VERSION 5.8 ;
BUSBITCHARS "[]" ;
DIVIDERCHAR "/" ;
UNITS
    DATABASE MICRONS 1000 ;
END UNITS

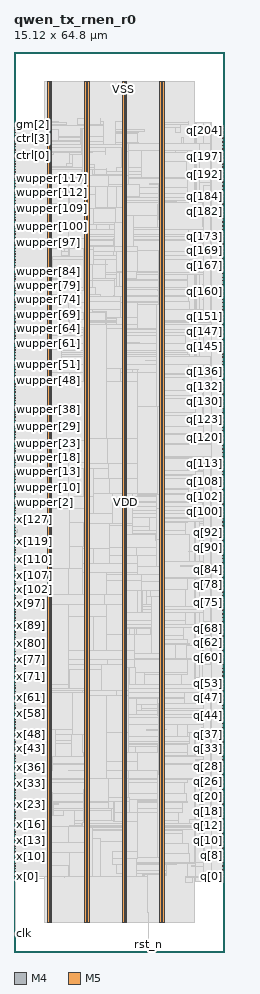
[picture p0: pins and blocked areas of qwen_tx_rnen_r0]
MACRO qwen_tx_rnen_r0
  FOREIGN qwen_tx_rnen_r0 0 0 ;
  CLASS BLOCK ;
  SIZE 15.12 BY 64.8 ;
  PIN clk
    DIRECTION INPUT ;
    USE SIGNAL ;
    PORT
      LAYER M4 ;
        RECT  0.054 1.296 0.138 1.32 ;
    END
    PORT
      LAYER M4 ;
        RECT  0.108 1.296 0.227 1.416 ;
    END
  END clk
  PIN ctrl[0]
    DIRECTION INPUT ;
    USE SIGNAL ;
    PORT
      LAYER M4 ;
        RECT  0.054 57.36 0.138 57.384 ;
    END
  END ctrl[0]
  PIN ctrl[1]
    DIRECTION INPUT ;
    USE SIGNAL ;
    PORT
      LAYER M4 ;
        RECT  0.054 57.552 0.138 57.576 ;
    END
  END ctrl[1]
  PIN ctrl[2]
    DIRECTION INPUT ;
    USE SIGNAL ;
    PORT
      LAYER M4 ;
        RECT  0.054 57.744 0.138 57.768 ;
    END
  END ctrl[2]
  PIN ctrl[3]
    DIRECTION INPUT ;
    USE SIGNAL ;
    PORT
      LAYER M4 ;
        RECT  0.054 57.984 0.138 58.008 ;
    END
  END ctrl[3]
  PIN ctrl[4]
    DIRECTION INPUT ;
    USE SIGNAL ;
    PORT
      LAYER M4 ;
        RECT  0.054 58.176 0.138 58.2 ;
    END
  END ctrl[4]
  PIN ctrl[5]
    DIRECTION INPUT ;
    USE SIGNAL ;
    PORT
      LAYER M4 ;
        RECT  0.054 58.368 0.138 58.392 ;
    END
  END ctrl[5]
  PIN gm[0]
    DIRECTION INPUT ;
    USE SIGNAL ;
    PORT
      LAYER M4 ;
        RECT  0.054 58.56 0.138 58.584 ;
    END
  END gm[0]
  PIN gm[1]
    DIRECTION INPUT ;
    USE SIGNAL ;
    PORT
      LAYER M4 ;
        RECT  0.054 58.8 0.138 58.824 ;
    END
  END gm[1]
  PIN gm[2]
    DIRECTION INPUT ;
    USE SIGNAL ;
    PORT
      LAYER M4 ;
        RECT  0.054 58.992 0.138 59.016 ;
    END
  END gm[2]
  PIN gm[3]
    DIRECTION INPUT ;
    USE SIGNAL ;
    PORT
      LAYER M4 ;
        RECT  0.054 59.184 0.138 59.208 ;
    END
  END gm[3]
  PIN q[0]
    DIRECTION OUTPUT ;
    USE SIGNAL ;
    PORT
      LAYER M4 ;
        RECT  14.982 5.424 15.066 5.448 ;
    END
  END q[0]
  PIN q[100]
    DIRECTION OUTPUT ;
    USE SIGNAL ;
    PORT
      LAYER M4 ;
        RECT  14.982 31.728 15.066 31.752 ;
    END
  END q[100]
  PIN q[101]
    DIRECTION OUTPUT ;
    USE SIGNAL ;
    PORT
      LAYER M4 ;
        RECT  14.982 32.016 15.066 32.04 ;
    END
  END q[101]
  PIN q[102]
    DIRECTION OUTPUT ;
    USE SIGNAL ;
    PORT
      LAYER M4 ;
        RECT  14.982 32.256 15.066 32.28 ;
    END
  END q[102]
  PIN q[103]
    DIRECTION OUTPUT ;
    USE SIGNAL ;
    PORT
      LAYER M4 ;
        RECT  14.982 32.496 15.066 32.52 ;
    END
  END q[103]
  PIN q[104]
    DIRECTION OUTPUT ;
    USE SIGNAL ;
    PORT
      LAYER M4 ;
        RECT  14.982 32.784 15.066 32.808 ;
    END
  END q[104]
  PIN q[105]
    DIRECTION OUTPUT ;
    USE SIGNAL ;
    PORT
      LAYER M4 ;
        RECT  14.982 33.024 15.066 33.048 ;
    END
  END q[105]
  PIN q[106]
    DIRECTION OUTPUT ;
    USE SIGNAL ;
    PORT
      LAYER M4 ;
        RECT  14.982 33.312 15.066 33.336 ;
    END
  END q[106]
  PIN q[107]
    DIRECTION OUTPUT ;
    USE SIGNAL ;
    PORT
      LAYER M4 ;
        RECT  14.982 33.552 15.066 33.576 ;
    END
  END q[107]
  PIN q[108]
    DIRECTION OUTPUT ;
    USE SIGNAL ;
    PORT
      LAYER M4 ;
        RECT  14.982 33.84 15.066 33.864 ;
    END
  END q[108]
  PIN q[109]
    DIRECTION OUTPUT ;
    USE SIGNAL ;
    PORT
      LAYER M4 ;
        RECT  14.982 34.08 15.066 34.104 ;
    END
  END q[109]
  PIN q[10]
    DIRECTION OUTPUT ;
    USE SIGNAL ;
    PORT
      LAYER M4 ;
        RECT  14.982 8.016 15.066 8.04 ;
    END
  END q[10]
  PIN q[110]
    DIRECTION OUTPUT ;
    USE SIGNAL ;
    PORT
      LAYER M4 ;
        RECT  14.982 34.368 15.066 34.392 ;
    END
  END q[110]
  PIN q[111]
    DIRECTION OUTPUT ;
    USE SIGNAL ;
    PORT
      LAYER M4 ;
        RECT  14.982 34.608 15.066 34.632 ;
    END
  END q[111]
  PIN q[112]
    DIRECTION OUTPUT ;
    USE SIGNAL ;
    PORT
      LAYER M4 ;
        RECT  14.982 34.896 15.066 34.92 ;
    END
  END q[112]
  PIN q[113]
    DIRECTION OUTPUT ;
    USE SIGNAL ;
    PORT
      LAYER M4 ;
        RECT  14.982 35.136 15.066 35.16 ;
    END
  END q[113]
  PIN q[114]
    DIRECTION OUTPUT ;
    USE SIGNAL ;
    PORT
      LAYER M4 ;
        RECT  14.982 35.424 15.066 35.448 ;
    END
  END q[114]
  PIN q[115]
    DIRECTION OUTPUT ;
    USE SIGNAL ;
    PORT
      LAYER M4 ;
        RECT  14.982 35.664 15.066 35.688 ;
    END
  END q[115]
  PIN q[116]
    DIRECTION OUTPUT ;
    USE SIGNAL ;
    PORT
      LAYER M4 ;
        RECT  14.982 35.952 15.066 35.976 ;
    END
  END q[116]
  PIN q[117]
    DIRECTION OUTPUT ;
    USE SIGNAL ;
    PORT
      LAYER M4 ;
        RECT  14.982 36.192 15.066 36.216 ;
    END
  END q[117]
  PIN q[118]
    DIRECTION OUTPUT ;
    USE SIGNAL ;
    PORT
      LAYER M4 ;
        RECT  14.982 36.48 15.066 36.504 ;
    END
  END q[118]
  PIN q[119]
    DIRECTION OUTPUT ;
    USE SIGNAL ;
    PORT
      LAYER M4 ;
        RECT  14.982 36.72 15.066 36.744 ;
    END
  END q[119]
  PIN q[11]
    DIRECTION OUTPUT ;
    USE SIGNAL ;
    PORT
      LAYER M4 ;
        RECT  14.982 8.304 15.066 8.328 ;
    END
  END q[11]
  PIN q[120]
    DIRECTION OUTPUT ;
    USE SIGNAL ;
    PORT
      LAYER M4 ;
        RECT  14.982 37.008 15.066 37.032 ;
    END
  END q[120]
  PIN q[121]
    DIRECTION OUTPUT ;
    USE SIGNAL ;
    PORT
      LAYER M4 ;
        RECT  14.982 37.248 15.066 37.272 ;
    END
  END q[121]
  PIN q[122]
    DIRECTION OUTPUT ;
    USE SIGNAL ;
    PORT
      LAYER M4 ;
        RECT  14.982 37.536 15.066 37.56 ;
    END
  END q[122]
  PIN q[123]
    DIRECTION OUTPUT ;
    USE SIGNAL ;
    PORT
      LAYER M4 ;
        RECT  14.982 37.776 15.066 37.8 ;
    END
  END q[123]
  PIN q[124]
    DIRECTION OUTPUT ;
    USE SIGNAL ;
    PORT
      LAYER M4 ;
        RECT  14.982 38.064 15.066 38.088 ;
    END
  END q[124]
  PIN q[125]
    DIRECTION OUTPUT ;
    USE SIGNAL ;
    PORT
      LAYER M4 ;
        RECT  14.982 38.304 15.066 38.328 ;
    END
  END q[125]
  PIN q[126]
    DIRECTION OUTPUT ;
    USE SIGNAL ;
    PORT
      LAYER M4 ;
        RECT  14.982 38.592 15.066 38.616 ;
    END
  END q[126]
  PIN q[127]
    DIRECTION OUTPUT ;
    USE SIGNAL ;
    PORT
      LAYER M4 ;
        RECT  14.982 38.832 15.066 38.856 ;
    END
  END q[127]
  PIN q[128]
    DIRECTION OUTPUT ;
    USE SIGNAL ;
    PORT
      LAYER M4 ;
        RECT  14.982 39.12 15.066 39.144 ;
    END
  END q[128]
  PIN q[129]
    DIRECTION OUTPUT ;
    USE SIGNAL ;
    PORT
      LAYER M4 ;
        RECT  14.982 39.36 15.066 39.384 ;
    END
  END q[129]
  PIN q[12]
    DIRECTION OUTPUT ;
    USE SIGNAL ;
    PORT
      LAYER M4 ;
        RECT  14.982 8.544 15.066 8.568 ;
    END
  END q[12]
  PIN q[130]
    DIRECTION OUTPUT ;
    USE SIGNAL ;
    PORT
      LAYER M4 ;
        RECT  14.982 39.648 15.066 39.672 ;
    END
  END q[130]
  PIN q[131]
    DIRECTION OUTPUT ;
    USE SIGNAL ;
    PORT
      LAYER M4 ;
        RECT  14.982 39.888 15.066 39.912 ;
    END
  END q[131]
  PIN q[132]
    DIRECTION OUTPUT ;
    USE SIGNAL ;
    PORT
      LAYER M4 ;
        RECT  14.982 40.176 15.066 40.2 ;
    END
  END q[132]
  PIN q[133]
    DIRECTION OUTPUT ;
    USE SIGNAL ;
    PORT
      LAYER M4 ;
        RECT  14.982 40.416 15.066 40.44 ;
    END
  END q[133]
  PIN q[134]
    DIRECTION OUTPUT ;
    USE SIGNAL ;
    PORT
      LAYER M4 ;
        RECT  14.982 40.704 15.066 40.728 ;
    END
  END q[134]
  PIN q[135]
    DIRECTION OUTPUT ;
    USE SIGNAL ;
    PORT
      LAYER M4 ;
        RECT  14.982 40.944 15.066 40.968 ;
    END
  END q[135]
  PIN q[136]
    DIRECTION OUTPUT ;
    USE SIGNAL ;
    PORT
      LAYER M4 ;
        RECT  14.982 41.232 15.066 41.256 ;
    END
  END q[136]
  PIN q[137]
    DIRECTION OUTPUT ;
    USE SIGNAL ;
    PORT
      LAYER M4 ;
        RECT  14.982 41.472 15.066 41.496 ;
    END
  END q[137]
  PIN q[138]
    DIRECTION OUTPUT ;
    USE SIGNAL ;
    PORT
      LAYER M4 ;
        RECT  14.982 41.76 15.066 41.784 ;
    END
  END q[138]
  PIN q[139]
    DIRECTION OUTPUT ;
    USE SIGNAL ;
    PORT
      LAYER M4 ;
        RECT  14.982 42 15.066 42.024 ;
    END
  END q[139]
  PIN q[13]
    DIRECTION OUTPUT ;
    USE SIGNAL ;
    PORT
      LAYER M4 ;
        RECT  14.982 8.832 15.066 8.856 ;
    END
  END q[13]
  PIN q[140]
    DIRECTION OUTPUT ;
    USE SIGNAL ;
    PORT
      LAYER M4 ;
        RECT  14.982 42.288 15.066 42.312 ;
    END
  END q[140]
  PIN q[141]
    DIRECTION OUTPUT ;
    USE SIGNAL ;
    PORT
      LAYER M4 ;
        RECT  14.982 42.528 15.066 42.552 ;
    END
  END q[141]
  PIN q[142]
    DIRECTION OUTPUT ;
    USE SIGNAL ;
    PORT
      LAYER M4 ;
        RECT  14.982 42.816 15.066 42.84 ;
    END
  END q[142]
  PIN q[143]
    DIRECTION OUTPUT ;
    USE SIGNAL ;
    PORT
      LAYER M4 ;
        RECT  14.982 43.056 15.066 43.08 ;
    END
  END q[143]
  PIN q[144]
    DIRECTION OUTPUT ;
    USE SIGNAL ;
    PORT
      LAYER M4 ;
        RECT  14.982 43.296 15.066 43.32 ;
    END
  END q[144]
  PIN q[145]
    DIRECTION OUTPUT ;
    USE SIGNAL ;
    PORT
      LAYER M4 ;
        RECT  14.982 43.584 15.066 43.608 ;
    END
  END q[145]
  PIN q[146]
    DIRECTION OUTPUT ;
    USE SIGNAL ;
    PORT
      LAYER M4 ;
        RECT  14.982 43.824 15.066 43.848 ;
    END
  END q[146]
  PIN q[147]
    DIRECTION OUTPUT ;
    USE SIGNAL ;
    PORT
      LAYER M4 ;
        RECT  14.982 44.112 15.066 44.136 ;
    END
  END q[147]
  PIN q[148]
    DIRECTION OUTPUT ;
    USE SIGNAL ;
    PORT
      LAYER M4 ;
        RECT  14.982 44.352 15.066 44.376 ;
    END
  END q[148]
  PIN q[149]
    DIRECTION OUTPUT ;
    USE SIGNAL ;
    PORT
      LAYER M4 ;
        RECT  14.982 44.64 15.066 44.664 ;
    END
  END q[149]
  PIN q[14]
    DIRECTION OUTPUT ;
    USE SIGNAL ;
    PORT
      LAYER M4 ;
        RECT  14.982 9.072 15.066 9.096 ;
    END
  END q[14]
  PIN q[150]
    DIRECTION OUTPUT ;
    USE SIGNAL ;
    PORT
      LAYER M4 ;
        RECT  14.982 44.88 15.066 44.904 ;
    END
  END q[150]
  PIN q[151]
    DIRECTION OUTPUT ;
    USE SIGNAL ;
    PORT
      LAYER M4 ;
        RECT  14.982 45.168 15.066 45.192 ;
    END
  END q[151]
  PIN q[152]
    DIRECTION OUTPUT ;
    USE SIGNAL ;
    PORT
      LAYER M4 ;
        RECT  14.982 45.408 15.066 45.432 ;
    END
  END q[152]
  PIN q[153]
    DIRECTION OUTPUT ;
    USE SIGNAL ;
    PORT
      LAYER M4 ;
        RECT  14.982 45.696 15.066 45.72 ;
    END
  END q[153]
  PIN q[154]
    DIRECTION OUTPUT ;
    USE SIGNAL ;
    PORT
      LAYER M4 ;
        RECT  14.982 45.936 15.066 45.96 ;
    END
  END q[154]
  PIN q[155]
    DIRECTION OUTPUT ;
    USE SIGNAL ;
    PORT
      LAYER M4 ;
        RECT  14.982 46.224 15.066 46.248 ;
    END
  END q[155]
  PIN q[156]
    DIRECTION OUTPUT ;
    USE SIGNAL ;
    PORT
      LAYER M4 ;
        RECT  14.982 46.464 15.066 46.488 ;
    END
  END q[156]
  PIN q[157]
    DIRECTION OUTPUT ;
    USE SIGNAL ;
    PORT
      LAYER M4 ;
        RECT  14.982 46.752 15.066 46.776 ;
    END
  END q[157]
  PIN q[158]
    DIRECTION OUTPUT ;
    USE SIGNAL ;
    PORT
      LAYER M4 ;
        RECT  14.982 46.992 15.066 47.016 ;
    END
  END q[158]
  PIN q[159]
    DIRECTION OUTPUT ;
    USE SIGNAL ;
    PORT
      LAYER M4 ;
        RECT  14.982 47.28 15.066 47.304 ;
    END
  END q[159]
  PIN q[15]
    DIRECTION OUTPUT ;
    USE SIGNAL ;
    PORT
      LAYER M4 ;
        RECT  14.982 9.36 15.066 9.384 ;
    END
  END q[15]
  PIN q[160]
    DIRECTION OUTPUT ;
    USE SIGNAL ;
    PORT
      LAYER M4 ;
        RECT  14.982 47.52 15.066 47.544 ;
    END
  END q[160]
  PIN q[161]
    DIRECTION OUTPUT ;
    USE SIGNAL ;
    PORT
      LAYER M4 ;
        RECT  14.982 47.808 15.066 47.832 ;
    END
  END q[161]
  PIN q[162]
    DIRECTION OUTPUT ;
    USE SIGNAL ;
    PORT
      LAYER M4 ;
        RECT  14.982 48.048 15.066 48.072 ;
    END
  END q[162]
  PIN q[163]
    DIRECTION OUTPUT ;
    USE SIGNAL ;
    PORT
      LAYER M4 ;
        RECT  14.982 48.336 15.066 48.36 ;
    END
  END q[163]
  PIN q[164]
    DIRECTION OUTPUT ;
    USE SIGNAL ;
    PORT
      LAYER M4 ;
        RECT  14.982 48.576 15.066 48.6 ;
    END
  END q[164]
  PIN q[165]
    DIRECTION OUTPUT ;
    USE SIGNAL ;
    PORT
      LAYER M4 ;
        RECT  14.982 48.864 15.066 48.888 ;
    END
  END q[165]
  PIN q[166]
    DIRECTION OUTPUT ;
    USE SIGNAL ;
    PORT
      LAYER M4 ;
        RECT  14.982 49.104 15.066 49.128 ;
    END
  END q[166]
  PIN q[167]
    DIRECTION OUTPUT ;
    USE SIGNAL ;
    PORT
      LAYER M4 ;
        RECT  14.982 49.392 15.066 49.416 ;
    END
  END q[167]
  PIN q[168]
    DIRECTION OUTPUT ;
    USE SIGNAL ;
    PORT
      LAYER M4 ;
        RECT  14.982 49.632 15.066 49.656 ;
    END
  END q[168]
  PIN q[169]
    DIRECTION OUTPUT ;
    USE SIGNAL ;
    PORT
      LAYER M4 ;
        RECT  14.982 49.92 15.066 49.944 ;
    END
  END q[169]
  PIN q[16]
    DIRECTION OUTPUT ;
    USE SIGNAL ;
    PORT
      LAYER M4 ;
        RECT  14.982 9.6 15.066 9.624 ;
    END
  END q[16]
  PIN q[170]
    DIRECTION OUTPUT ;
    USE SIGNAL ;
    PORT
      LAYER M4 ;
        RECT  14.982 50.16 15.066 50.184 ;
    END
  END q[170]
  PIN q[171]
    DIRECTION OUTPUT ;
    USE SIGNAL ;
    PORT
      LAYER M4 ;
        RECT  14.982 50.448 15.066 50.472 ;
    END
  END q[171]
  PIN q[172]
    DIRECTION OUTPUT ;
    USE SIGNAL ;
    PORT
      LAYER M4 ;
        RECT  14.982 50.688 15.066 50.712 ;
    END
  END q[172]
  PIN q[173]
    DIRECTION OUTPUT ;
    USE SIGNAL ;
    PORT
      LAYER M4 ;
        RECT  14.982 50.976 15.066 51 ;
    END
  END q[173]
  PIN q[174]
    DIRECTION OUTPUT ;
    USE SIGNAL ;
    PORT
      LAYER M4 ;
        RECT  14.982 51.216 15.066 51.24 ;
    END
  END q[174]
  PIN q[175]
    DIRECTION OUTPUT ;
    USE SIGNAL ;
    PORT
      LAYER M4 ;
        RECT  14.982 51.504 15.066 51.528 ;
    END
  END q[175]
  PIN q[176]
    DIRECTION OUTPUT ;
    USE SIGNAL ;
    PORT
      LAYER M4 ;
        RECT  14.982 51.744 15.066 51.768 ;
    END
  END q[176]
  PIN q[177]
    DIRECTION OUTPUT ;
    USE SIGNAL ;
    PORT
      LAYER M4 ;
        RECT  14.982 52.032 15.066 52.056 ;
    END
  END q[177]
  PIN q[178]
    DIRECTION OUTPUT ;
    USE SIGNAL ;
    PORT
      LAYER M4 ;
        RECT  14.982 52.272 15.066 52.296 ;
    END
  END q[178]
  PIN q[179]
    DIRECTION OUTPUT ;
    USE SIGNAL ;
    PORT
      LAYER M4 ;
        RECT  14.982 52.56 15.066 52.584 ;
    END
  END q[179]
  PIN q[17]
    DIRECTION OUTPUT ;
    USE SIGNAL ;
    PORT
      LAYER M4 ;
        RECT  14.982 9.888 15.066 9.912 ;
    END
  END q[17]
  PIN q[180]
    DIRECTION OUTPUT ;
    USE SIGNAL ;
    PORT
      LAYER M4 ;
        RECT  14.982 52.8 15.066 52.824 ;
    END
  END q[180]
  PIN q[181]
    DIRECTION OUTPUT ;
    USE SIGNAL ;
    PORT
      LAYER M4 ;
        RECT  14.982 53.088 15.066 53.112 ;
    END
  END q[181]
  PIN q[182]
    DIRECTION OUTPUT ;
    USE SIGNAL ;
    PORT
      LAYER M4 ;
        RECT  14.982 53.328 15.066 53.352 ;
    END
  END q[182]
  PIN q[183]
    DIRECTION OUTPUT ;
    USE SIGNAL ;
    PORT
      LAYER M4 ;
        RECT  14.982 53.616 15.066 53.64 ;
    END
  END q[183]
  PIN q[184]
    DIRECTION OUTPUT ;
    USE SIGNAL ;
    PORT
      LAYER M4 ;
        RECT  14.982 53.856 15.066 53.88 ;
    END
  END q[184]
  PIN q[185]
    DIRECTION OUTPUT ;
    USE SIGNAL ;
    PORT
      LAYER M4 ;
        RECT  14.982 54.096 15.066 54.12 ;
    END
  END q[185]
  PIN q[186]
    DIRECTION OUTPUT ;
    USE SIGNAL ;
    PORT
      LAYER M4 ;
        RECT  14.982 54.384 15.066 54.408 ;
    END
  END q[186]
  PIN q[187]
    DIRECTION OUTPUT ;
    USE SIGNAL ;
    PORT
      LAYER M4 ;
        RECT  14.982 54.624 15.066 54.648 ;
    END
  END q[187]
  PIN q[188]
    DIRECTION OUTPUT ;
    USE SIGNAL ;
    PORT
      LAYER M4 ;
        RECT  14.982 54.912 15.066 54.936 ;
    END
  END q[188]
  PIN q[189]
    DIRECTION OUTPUT ;
    USE SIGNAL ;
    PORT
      LAYER M4 ;
        RECT  14.982 55.152 15.066 55.176 ;
    END
  END q[189]
  PIN q[18]
    DIRECTION OUTPUT ;
    USE SIGNAL ;
    PORT
      LAYER M4 ;
        RECT  14.982 10.128 15.066 10.152 ;
    END
  END q[18]
  PIN q[190]
    DIRECTION OUTPUT ;
    USE SIGNAL ;
    PORT
      LAYER M4 ;
        RECT  14.982 55.44 15.066 55.464 ;
    END
  END q[190]
  PIN q[191]
    DIRECTION OUTPUT ;
    USE SIGNAL ;
    PORT
      LAYER M4 ;
        RECT  14.982 55.68 15.066 55.704 ;
    END
  END q[191]
  PIN q[192]
    DIRECTION OUTPUT ;
    USE SIGNAL ;
    PORT
      LAYER M4 ;
        RECT  14.982 55.968 15.066 55.992 ;
    END
  END q[192]
  PIN q[193]
    DIRECTION OUTPUT ;
    USE SIGNAL ;
    PORT
      LAYER M4 ;
        RECT  14.982 56.208 15.066 56.232 ;
    END
  END q[193]
  PIN q[194]
    DIRECTION OUTPUT ;
    USE SIGNAL ;
    PORT
      LAYER M4 ;
        RECT  14.982 56.496 15.066 56.52 ;
    END
  END q[194]
  PIN q[195]
    DIRECTION OUTPUT ;
    USE SIGNAL ;
    PORT
      LAYER M4 ;
        RECT  14.982 56.736 15.066 56.76 ;
    END
  END q[195]
  PIN q[196]
    DIRECTION OUTPUT ;
    USE SIGNAL ;
    PORT
      LAYER M4 ;
        RECT  14.982 57.024 15.066 57.048 ;
    END
  END q[196]
  PIN q[197]
    DIRECTION OUTPUT ;
    USE SIGNAL ;
    PORT
      LAYER M4 ;
        RECT  14.982 57.264 15.066 57.288 ;
    END
  END q[197]
  PIN q[198]
    DIRECTION OUTPUT ;
    USE SIGNAL ;
    PORT
      LAYER M4 ;
        RECT  14.982 57.552 15.066 57.576 ;
    END
  END q[198]
  PIN q[199]
    DIRECTION OUTPUT ;
    USE SIGNAL ;
    PORT
      LAYER M4 ;
        RECT  14.982 57.792 15.066 57.816 ;
    END
  END q[199]
  PIN q[19]
    DIRECTION OUTPUT ;
    USE SIGNAL ;
    PORT
      LAYER M4 ;
        RECT  14.982 10.416 15.066 10.44 ;
    END
  END q[19]
  PIN q[1]
    DIRECTION OUTPUT ;
    USE SIGNAL ;
    PORT
      LAYER M4 ;
        RECT  14.982 5.664 15.066 5.688 ;
    END
  END q[1]
  PIN q[200]
    DIRECTION OUTPUT ;
    USE SIGNAL ;
    PORT
      LAYER M4 ;
        RECT  14.982 58.08 15.066 58.104 ;
    END
  END q[200]
  PIN q[201]
    DIRECTION OUTPUT ;
    USE SIGNAL ;
    PORT
      LAYER M4 ;
        RECT  14.982 58.32 15.066 58.344 ;
    END
  END q[201]
  PIN q[202]
    DIRECTION OUTPUT ;
    USE SIGNAL ;
    PORT
      LAYER M4 ;
        RECT  14.982 58.608 15.066 58.632 ;
    END
  END q[202]
  PIN q[203]
    DIRECTION OUTPUT ;
    USE SIGNAL ;
    PORT
      LAYER M4 ;
        RECT  14.982 58.848 15.066 58.872 ;
    END
  END q[203]
  PIN q[204]
    DIRECTION OUTPUT ;
    USE SIGNAL ;
    PORT
      LAYER M4 ;
        RECT  14.982 59.136 15.066 59.16 ;
    END
  END q[204]
  PIN q[205]
    DIRECTION OUTPUT ;
    USE SIGNAL ;
    PORT
      LAYER M4 ;
        RECT  14.982 59.376 15.066 59.4 ;
    END
  END q[205]
  PIN q[20]
    DIRECTION OUTPUT ;
    USE SIGNAL ;
    PORT
      LAYER M4 ;
        RECT  14.982 10.656 15.066 10.68 ;
    END
  END q[20]
  PIN q[21]
    DIRECTION OUTPUT ;
    USE SIGNAL ;
    PORT
      LAYER M4 ;
        RECT  14.982 10.896 15.066 10.92 ;
    END
  END q[21]
  PIN q[22]
    DIRECTION OUTPUT ;
    USE SIGNAL ;
    PORT
      LAYER M4 ;
        RECT  14.982 11.184 15.066 11.208 ;
    END
  END q[22]
  PIN q[23]
    DIRECTION OUTPUT ;
    USE SIGNAL ;
    PORT
      LAYER M4 ;
        RECT  14.982 11.424 15.066 11.448 ;
    END
  END q[23]
  PIN q[24]
    DIRECTION OUTPUT ;
    USE SIGNAL ;
    PORT
      LAYER M4 ;
        RECT  14.982 11.712 15.066 11.736 ;
    END
  END q[24]
  PIN q[25]
    DIRECTION OUTPUT ;
    USE SIGNAL ;
    PORT
      LAYER M4 ;
        RECT  14.982 11.952 15.066 11.976 ;
    END
  END q[25]
  PIN q[26]
    DIRECTION OUTPUT ;
    USE SIGNAL ;
    PORT
      LAYER M4 ;
        RECT  14.982 12.24 15.066 12.264 ;
    END
  END q[26]
  PIN q[27]
    DIRECTION OUTPUT ;
    USE SIGNAL ;
    PORT
      LAYER M4 ;
        RECT  14.982 12.48 15.066 12.504 ;
    END
  END q[27]
  PIN q[28]
    DIRECTION OUTPUT ;
    USE SIGNAL ;
    PORT
      LAYER M4 ;
        RECT  14.982 12.768 15.066 12.792 ;
    END
  END q[28]
  PIN q[29]
    DIRECTION OUTPUT ;
    USE SIGNAL ;
    PORT
      LAYER M4 ;
        RECT  14.982 13.008 15.066 13.032 ;
    END
  END q[29]
  PIN q[2]
    DIRECTION OUTPUT ;
    USE SIGNAL ;
    PORT
      LAYER M4 ;
        RECT  14.982 5.904 15.066 5.928 ;
    END
  END q[2]
  PIN q[30]
    DIRECTION OUTPUT ;
    USE SIGNAL ;
    PORT
      LAYER M4 ;
        RECT  14.982 13.296 15.066 13.32 ;
    END
  END q[30]
  PIN q[31]
    DIRECTION OUTPUT ;
    USE SIGNAL ;
    PORT
      LAYER M4 ;
        RECT  14.982 13.536 15.066 13.56 ;
    END
  END q[31]
  PIN q[32]
    DIRECTION OUTPUT ;
    USE SIGNAL ;
    PORT
      LAYER M4 ;
        RECT  14.982 13.824 15.066 13.848 ;
    END
  END q[32]
  PIN q[33]
    DIRECTION OUTPUT ;
    USE SIGNAL ;
    PORT
      LAYER M4 ;
        RECT  14.982 14.064 15.066 14.088 ;
    END
  END q[33]
  PIN q[34]
    DIRECTION OUTPUT ;
    USE SIGNAL ;
    PORT
      LAYER M4 ;
        RECT  14.982 14.352 15.066 14.376 ;
    END
  END q[34]
  PIN q[35]
    DIRECTION OUTPUT ;
    USE SIGNAL ;
    PORT
      LAYER M4 ;
        RECT  14.982 14.592 15.066 14.616 ;
    END
  END q[35]
  PIN q[36]
    DIRECTION OUTPUT ;
    USE SIGNAL ;
    PORT
      LAYER M4 ;
        RECT  14.982 14.88 15.066 14.904 ;
    END
  END q[36]
  PIN q[37]
    DIRECTION OUTPUT ;
    USE SIGNAL ;
    PORT
      LAYER M4 ;
        RECT  14.982 15.12 15.066 15.144 ;
    END
  END q[37]
  PIN q[38]
    DIRECTION OUTPUT ;
    USE SIGNAL ;
    PORT
      LAYER M4 ;
        RECT  14.982 15.408 15.066 15.432 ;
    END
  END q[38]
  PIN q[39]
    DIRECTION OUTPUT ;
    USE SIGNAL ;
    PORT
      LAYER M4 ;
        RECT  14.982 15.648 15.066 15.672 ;
    END
  END q[39]
  PIN q[3]
    DIRECTION OUTPUT ;
    USE SIGNAL ;
    PORT
      LAYER M4 ;
        RECT  14.982 6.192 15.066 6.216 ;
    END
  END q[3]
  PIN q[40]
    DIRECTION OUTPUT ;
    USE SIGNAL ;
    PORT
      LAYER M4 ;
        RECT  14.982 15.936 15.066 15.96 ;
    END
  END q[40]
  PIN q[41]
    DIRECTION OUTPUT ;
    USE SIGNAL ;
    PORT
      LAYER M4 ;
        RECT  14.982 16.176 15.066 16.2 ;
    END
  END q[41]
  PIN q[42]
    DIRECTION OUTPUT ;
    USE SIGNAL ;
    PORT
      LAYER M4 ;
        RECT  14.982 16.464 15.066 16.488 ;
    END
  END q[42]
  PIN q[43]
    DIRECTION OUTPUT ;
    USE SIGNAL ;
    PORT
      LAYER M4 ;
        RECT  14.982 16.704 15.066 16.728 ;
    END
  END q[43]
  PIN q[44]
    DIRECTION OUTPUT ;
    USE SIGNAL ;
    PORT
      LAYER M4 ;
        RECT  14.982 16.992 15.066 17.016 ;
    END
  END q[44]
  PIN q[45]
    DIRECTION OUTPUT ;
    USE SIGNAL ;
    PORT
      LAYER M4 ;
        RECT  14.982 17.232 15.066 17.256 ;
    END
  END q[45]
  PIN q[46]
    DIRECTION OUTPUT ;
    USE SIGNAL ;
    PORT
      LAYER M4 ;
        RECT  14.982 17.52 15.066 17.544 ;
    END
  END q[46]
  PIN q[47]
    DIRECTION OUTPUT ;
    USE SIGNAL ;
    PORT
      LAYER M4 ;
        RECT  14.982 17.76 15.066 17.784 ;
    END
  END q[47]
  PIN q[48]
    DIRECTION OUTPUT ;
    USE SIGNAL ;
    PORT
      LAYER M4 ;
        RECT  14.982 18.048 15.066 18.072 ;
    END
  END q[48]
  PIN q[49]
    DIRECTION OUTPUT ;
    USE SIGNAL ;
    PORT
      LAYER M4 ;
        RECT  14.982 18.288 15.066 18.312 ;
    END
  END q[49]
  PIN q[4]
    DIRECTION OUTPUT ;
    USE SIGNAL ;
    PORT
      LAYER M4 ;
        RECT  14.982 6.432 15.066 6.456 ;
    END
  END q[4]
  PIN q[50]
    DIRECTION OUTPUT ;
    USE SIGNAL ;
    PORT
      LAYER M4 ;
        RECT  14.982 18.576 15.066 18.6 ;
    END
  END q[50]
  PIN q[51]
    DIRECTION OUTPUT ;
    USE SIGNAL ;
    PORT
      LAYER M4 ;
        RECT  14.982 18.816 15.066 18.84 ;
    END
  END q[51]
  PIN q[52]
    DIRECTION OUTPUT ;
    USE SIGNAL ;
    PORT
      LAYER M4 ;
        RECT  14.982 19.104 15.066 19.128 ;
    END
  END q[52]
  PIN q[53]
    DIRECTION OUTPUT ;
    USE SIGNAL ;
    PORT
      LAYER M4 ;
        RECT  14.982 19.344 15.066 19.368 ;
    END
  END q[53]
  PIN q[54]
    DIRECTION OUTPUT ;
    USE SIGNAL ;
    PORT
      LAYER M4 ;
        RECT  14.982 19.632 15.066 19.656 ;
    END
  END q[54]
  PIN q[55]
    DIRECTION OUTPUT ;
    USE SIGNAL ;
    PORT
      LAYER M4 ;
        RECT  14.982 19.872 15.066 19.896 ;
    END
  END q[55]
  PIN q[56]
    DIRECTION OUTPUT ;
    USE SIGNAL ;
    PORT
      LAYER M4 ;
        RECT  14.982 20.16 15.066 20.184 ;
    END
  END q[56]
  PIN q[57]
    DIRECTION OUTPUT ;
    USE SIGNAL ;
    PORT
      LAYER M4 ;
        RECT  14.982 20.4 15.066 20.424 ;
    END
  END q[57]
  PIN q[58]
    DIRECTION OUTPUT ;
    USE SIGNAL ;
    PORT
      LAYER M4 ;
        RECT  14.982 20.688 15.066 20.712 ;
    END
  END q[58]
  PIN q[59]
    DIRECTION OUTPUT ;
    USE SIGNAL ;
    PORT
      LAYER M4 ;
        RECT  14.982 20.928 15.066 20.952 ;
    END
  END q[59]
  PIN q[5]
    DIRECTION OUTPUT ;
    USE SIGNAL ;
    PORT
      LAYER M4 ;
        RECT  14.982 6.72 15.066 6.744 ;
    END
  END q[5]
  PIN q[60]
    DIRECTION OUTPUT ;
    USE SIGNAL ;
    PORT
      LAYER M4 ;
        RECT  14.982 21.216 15.066 21.24 ;
    END
  END q[60]
  PIN q[61]
    DIRECTION OUTPUT ;
    USE SIGNAL ;
    PORT
      LAYER M4 ;
        RECT  14.982 21.456 15.066 21.48 ;
    END
  END q[61]
  PIN q[62]
    DIRECTION OUTPUT ;
    USE SIGNAL ;
    PORT
      LAYER M4 ;
        RECT  14.982 21.696 15.066 21.72 ;
    END
  END q[62]
  PIN q[63]
    DIRECTION OUTPUT ;
    USE SIGNAL ;
    PORT
      LAYER M4 ;
        RECT  14.982 21.984 15.066 22.008 ;
    END
  END q[63]
  PIN q[64]
    DIRECTION OUTPUT ;
    USE SIGNAL ;
    PORT
      LAYER M4 ;
        RECT  14.982 22.224 15.066 22.248 ;
    END
  END q[64]
  PIN q[65]
    DIRECTION OUTPUT ;
    USE SIGNAL ;
    PORT
      LAYER M4 ;
        RECT  14.982 22.512 15.066 22.536 ;
    END
  END q[65]
  PIN q[66]
    DIRECTION OUTPUT ;
    USE SIGNAL ;
    PORT
      LAYER M4 ;
        RECT  14.982 22.752 15.066 22.776 ;
    END
  END q[66]
  PIN q[67]
    DIRECTION OUTPUT ;
    USE SIGNAL ;
    PORT
      LAYER M4 ;
        RECT  14.982 23.04 15.066 23.064 ;
    END
  END q[67]
  PIN q[68]
    DIRECTION OUTPUT ;
    USE SIGNAL ;
    PORT
      LAYER M4 ;
        RECT  14.982 23.28 15.066 23.304 ;
    END
  END q[68]
  PIN q[69]
    DIRECTION OUTPUT ;
    USE SIGNAL ;
    PORT
      LAYER M4 ;
        RECT  14.982 23.568 15.066 23.592 ;
    END
  END q[69]
  PIN q[6]
    DIRECTION OUTPUT ;
    USE SIGNAL ;
    PORT
      LAYER M4 ;
        RECT  14.982 6.96 15.066 6.984 ;
    END
  END q[6]
  PIN q[70]
    DIRECTION OUTPUT ;
    USE SIGNAL ;
    PORT
      LAYER M4 ;
        RECT  14.982 23.808 15.066 23.832 ;
    END
  END q[70]
  PIN q[71]
    DIRECTION OUTPUT ;
    USE SIGNAL ;
    PORT
      LAYER M4 ;
        RECT  14.982 24.096 15.066 24.12 ;
    END
  END q[71]
  PIN q[72]
    DIRECTION OUTPUT ;
    USE SIGNAL ;
    PORT
      LAYER M4 ;
        RECT  14.982 24.336 15.066 24.36 ;
    END
  END q[72]
  PIN q[73]
    DIRECTION OUTPUT ;
    USE SIGNAL ;
    PORT
      LAYER M4 ;
        RECT  14.982 24.624 15.066 24.648 ;
    END
  END q[73]
  PIN q[74]
    DIRECTION OUTPUT ;
    USE SIGNAL ;
    PORT
      LAYER M4 ;
        RECT  14.982 24.864 15.066 24.888 ;
    END
  END q[74]
  PIN q[75]
    DIRECTION OUTPUT ;
    USE SIGNAL ;
    PORT
      LAYER M4 ;
        RECT  14.982 25.152 15.066 25.176 ;
    END
  END q[75]
  PIN q[76]
    DIRECTION OUTPUT ;
    USE SIGNAL ;
    PORT
      LAYER M4 ;
        RECT  14.982 25.392 15.066 25.416 ;
    END
  END q[76]
  PIN q[77]
    DIRECTION OUTPUT ;
    USE SIGNAL ;
    PORT
      LAYER M4 ;
        RECT  14.982 25.68 15.066 25.704 ;
    END
  END q[77]
  PIN q[78]
    DIRECTION OUTPUT ;
    USE SIGNAL ;
    PORT
      LAYER M4 ;
        RECT  14.982 25.92 15.066 25.944 ;
    END
  END q[78]
  PIN q[79]
    DIRECTION OUTPUT ;
    USE SIGNAL ;
    PORT
      LAYER M4 ;
        RECT  14.982 26.208 15.066 26.232 ;
    END
  END q[79]
  PIN q[7]
    DIRECTION OUTPUT ;
    USE SIGNAL ;
    PORT
      LAYER M4 ;
        RECT  14.982 7.248 15.066 7.272 ;
    END
  END q[7]
  PIN q[80]
    DIRECTION OUTPUT ;
    USE SIGNAL ;
    PORT
      LAYER M4 ;
        RECT  14.982 26.448 15.066 26.472 ;
    END
  END q[80]
  PIN q[81]
    DIRECTION OUTPUT ;
    USE SIGNAL ;
    PORT
      LAYER M4 ;
        RECT  14.982 26.736 15.066 26.76 ;
    END
  END q[81]
  PIN q[82]
    DIRECTION OUTPUT ;
    USE SIGNAL ;
    PORT
      LAYER M4 ;
        RECT  14.982 26.976 15.066 27 ;
    END
  END q[82]
  PIN q[83]
    DIRECTION OUTPUT ;
    USE SIGNAL ;
    PORT
      LAYER M4 ;
        RECT  14.982 27.264 15.066 27.288 ;
    END
  END q[83]
  PIN q[84]
    DIRECTION OUTPUT ;
    USE SIGNAL ;
    PORT
      LAYER M4 ;
        RECT  14.982 27.504 15.066 27.528 ;
    END
  END q[84]
  PIN q[85]
    DIRECTION OUTPUT ;
    USE SIGNAL ;
    PORT
      LAYER M4 ;
        RECT  14.982 27.792 15.066 27.816 ;
    END
  END q[85]
  PIN q[86]
    DIRECTION OUTPUT ;
    USE SIGNAL ;
    PORT
      LAYER M4 ;
        RECT  14.982 28.032 15.066 28.056 ;
    END
  END q[86]
  PIN q[87]
    DIRECTION OUTPUT ;
    USE SIGNAL ;
    PORT
      LAYER M4 ;
        RECT  14.982 28.32 15.066 28.344 ;
    END
  END q[87]
  PIN q[88]
    DIRECTION OUTPUT ;
    USE SIGNAL ;
    PORT
      LAYER M4 ;
        RECT  14.982 28.56 15.066 28.584 ;
    END
  END q[88]
  PIN q[89]
    DIRECTION OUTPUT ;
    USE SIGNAL ;
    PORT
      LAYER M4 ;
        RECT  14.982 28.848 15.066 28.872 ;
    END
  END q[89]
  PIN q[8]
    DIRECTION OUTPUT ;
    USE SIGNAL ;
    PORT
      LAYER M4 ;
        RECT  14.982 7.488 15.066 7.512 ;
    END
  END q[8]
  PIN q[90]
    DIRECTION OUTPUT ;
    USE SIGNAL ;
    PORT
      LAYER M4 ;
        RECT  14.982 29.088 15.066 29.112 ;
    END
  END q[90]
  PIN q[91]
    DIRECTION OUTPUT ;
    USE SIGNAL ;
    PORT
      LAYER M4 ;
        RECT  14.982 29.376 15.066 29.4 ;
    END
  END q[91]
  PIN q[92]
    DIRECTION OUTPUT ;
    USE SIGNAL ;
    PORT
      LAYER M4 ;
        RECT  14.982 29.616 15.066 29.64 ;
    END
  END q[92]
  PIN q[93]
    DIRECTION OUTPUT ;
    USE SIGNAL ;
    PORT
      LAYER M4 ;
        RECT  14.982 29.904 15.066 29.928 ;
    END
  END q[93]
  PIN q[94]
    DIRECTION OUTPUT ;
    USE SIGNAL ;
    PORT
      LAYER M4 ;
        RECT  14.982 30.144 15.066 30.168 ;
    END
  END q[94]
  PIN q[95]
    DIRECTION OUTPUT ;
    USE SIGNAL ;
    PORT
      LAYER M4 ;
        RECT  14.982 30.432 15.066 30.456 ;
    END
  END q[95]
  PIN q[96]
    DIRECTION OUTPUT ;
    USE SIGNAL ;
    PORT
      LAYER M4 ;
        RECT  14.982 30.672 15.066 30.696 ;
    END
  END q[96]
  PIN q[97]
    DIRECTION OUTPUT ;
    USE SIGNAL ;
    PORT
      LAYER M4 ;
        RECT  14.982 30.96 15.066 30.984 ;
    END
  END q[97]
  PIN q[98]
    DIRECTION OUTPUT ;
    USE SIGNAL ;
    PORT
      LAYER M4 ;
        RECT  14.982 31.2 15.066 31.224 ;
    END
  END q[98]
  PIN q[99]
    DIRECTION OUTPUT ;
    USE SIGNAL ;
    PORT
      LAYER M4 ;
        RECT  14.982 31.488 15.066 31.512 ;
    END
  END q[99]
  PIN q[9]
    DIRECTION OUTPUT ;
    USE SIGNAL ;
    PORT
      LAYER M4 ;
        RECT  14.982 7.776 15.066 7.8 ;
    END
  END q[9]
  PIN round
    DIRECTION INPUT ;
    USE SIGNAL ;
    PORT
      LAYER M4 ;
        RECT  0.054 59.376 0.138 59.4 ;
    END
  END round
  PIN rst_n
    DIRECTION INPUT ;
    USE SIGNAL ;
    PORT
      LAYER M5 ;
        RECT  9.696 0.054 9.72 0.138 ;
    END
    PORT
      LAYER M5 ;
        RECT  9.696 0.08 9.72 0.563 ;
    END
  END rst_n
  PIN wupper[0]
    DIRECTION INPUT ;
    USE SIGNAL ;
    PORT
      LAYER M4 ;
        RECT  0.054 31.392 0.138 31.416 ;
    END
  END wupper[0]
  PIN wupper[100]
    DIRECTION INPUT ;
    USE SIGNAL ;
    PORT
      LAYER M4 ;
        RECT  0.054 51.696 0.138 51.72 ;
    END
  END wupper[100]
  PIN wupper[101]
    DIRECTION INPUT ;
    USE SIGNAL ;
    PORT
      LAYER M4 ;
        RECT  0.054 51.888 0.138 51.912 ;
    END
  END wupper[101]
  PIN wupper[102]
    DIRECTION INPUT ;
    USE SIGNAL ;
    PORT
      LAYER M4 ;
        RECT  0.054 52.08 0.138 52.104 ;
    END
  END wupper[102]
  PIN wupper[103]
    DIRECTION INPUT ;
    USE SIGNAL ;
    PORT
      LAYER M4 ;
        RECT  0.054 52.272 0.138 52.296 ;
    END
  END wupper[103]
  PIN wupper[104]
    DIRECTION INPUT ;
    USE SIGNAL ;
    PORT
      LAYER M4 ;
        RECT  0.054 52.464 0.138 52.488 ;
    END
  END wupper[104]
  PIN wupper[105]
    DIRECTION INPUT ;
    USE SIGNAL ;
    PORT
      LAYER M4 ;
        RECT  0.054 52.704 0.138 52.728 ;
    END
  END wupper[105]
  PIN wupper[106]
    DIRECTION INPUT ;
    USE SIGNAL ;
    PORT
      LAYER M4 ;
        RECT  0.054 52.896 0.138 52.92 ;
    END
  END wupper[106]
  PIN wupper[107]
    DIRECTION INPUT ;
    USE SIGNAL ;
    PORT
      LAYER M4 ;
        RECT  0.054 53.088 0.138 53.112 ;
    END
  END wupper[107]
  PIN wupper[108]
    DIRECTION INPUT ;
    USE SIGNAL ;
    PORT
      LAYER M4 ;
        RECT  0.054 53.28 0.138 53.304 ;
    END
  END wupper[108]
  PIN wupper[109]
    DIRECTION INPUT ;
    USE SIGNAL ;
    PORT
      LAYER M4 ;
        RECT  0.054 53.52 0.138 53.544 ;
    END
  END wupper[109]
  PIN wupper[10]
    DIRECTION INPUT ;
    USE SIGNAL ;
    PORT
      LAYER M4 ;
        RECT  0.054 33.408 0.138 33.432 ;
    END
  END wupper[10]
  PIN wupper[110]
    DIRECTION INPUT ;
    USE SIGNAL ;
    PORT
      LAYER M4 ;
        RECT  0.054 53.712 0.138 53.736 ;
    END
  END wupper[110]
  PIN wupper[111]
    DIRECTION INPUT ;
    USE SIGNAL ;
    PORT
      LAYER M4 ;
        RECT  0.054 53.904 0.138 53.928 ;
    END
  END wupper[111]
  PIN wupper[112]
    DIRECTION INPUT ;
    USE SIGNAL ;
    PORT
      LAYER M4 ;
        RECT  0.054 54.096 0.138 54.12 ;
    END
  END wupper[112]
  PIN wupper[113]
    DIRECTION INPUT ;
    USE SIGNAL ;
    PORT
      LAYER M4 ;
        RECT  0.054 54.336 0.138 54.36 ;
    END
  END wupper[113]
  PIN wupper[114]
    DIRECTION INPUT ;
    USE SIGNAL ;
    PORT
      LAYER M4 ;
        RECT  0.054 54.528 0.138 54.552 ;
    END
  END wupper[114]
  PIN wupper[115]
    DIRECTION INPUT ;
    USE SIGNAL ;
    PORT
      LAYER M4 ;
        RECT  0.054 54.72 0.138 54.744 ;
    END
  END wupper[115]
  PIN wupper[116]
    DIRECTION INPUT ;
    USE SIGNAL ;
    PORT
      LAYER M4 ;
        RECT  0.054 54.912 0.138 54.936 ;
    END
  END wupper[116]
  PIN wupper[117]
    DIRECTION INPUT ;
    USE SIGNAL ;
    PORT
      LAYER M4 ;
        RECT  0.054 55.104 0.138 55.128 ;
    END
  END wupper[117]
  PIN wupper[118]
    DIRECTION INPUT ;
    USE SIGNAL ;
    PORT
      LAYER M4 ;
        RECT  0.054 55.344 0.138 55.368 ;
    END
  END wupper[118]
  PIN wupper[119]
    DIRECTION INPUT ;
    USE SIGNAL ;
    PORT
      LAYER M4 ;
        RECT  0.054 55.536 0.138 55.56 ;
    END
  END wupper[119]
  PIN wupper[11]
    DIRECTION INPUT ;
    USE SIGNAL ;
    PORT
      LAYER M4 ;
        RECT  0.054 33.6 0.138 33.624 ;
    END
  END wupper[11]
  PIN wupper[120]
    DIRECTION INPUT ;
    USE SIGNAL ;
    PORT
      LAYER M4 ;
        RECT  0.054 55.728 0.138 55.752 ;
    END
  END wupper[120]
  PIN wupper[121]
    DIRECTION INPUT ;
    USE SIGNAL ;
    PORT
      LAYER M4 ;
        RECT  0.054 55.92 0.138 55.944 ;
    END
  END wupper[121]
  PIN wupper[122]
    DIRECTION INPUT ;
    USE SIGNAL ;
    PORT
      LAYER M4 ;
        RECT  0.054 56.16 0.138 56.184 ;
    END
  END wupper[122]
  PIN wupper[123]
    DIRECTION INPUT ;
    USE SIGNAL ;
    PORT
      LAYER M4 ;
        RECT  0.054 56.352 0.138 56.376 ;
    END
  END wupper[123]
  PIN wupper[124]
    DIRECTION INPUT ;
    USE SIGNAL ;
    PORT
      LAYER M4 ;
        RECT  0.054 56.544 0.138 56.568 ;
    END
  END wupper[124]
  PIN wupper[125]
    DIRECTION INPUT ;
    USE SIGNAL ;
    PORT
      LAYER M4 ;
        RECT  0.054 56.736 0.138 56.76 ;
    END
  END wupper[125]
  PIN wupper[126]
    DIRECTION INPUT ;
    USE SIGNAL ;
    PORT
      LAYER M4 ;
        RECT  0.054 56.928 0.138 56.952 ;
    END
  END wupper[126]
  PIN wupper[127]
    DIRECTION INPUT ;
    USE SIGNAL ;
    PORT
      LAYER M4 ;
        RECT  0.054 57.168 0.138 57.192 ;
    END
  END wupper[127]
  PIN wupper[12]
    DIRECTION INPUT ;
    USE SIGNAL ;
    PORT
      LAYER M4 ;
        RECT  0.054 33.792 0.138 33.816 ;
    END
  END wupper[12]
  PIN wupper[13]
    DIRECTION INPUT ;
    USE SIGNAL ;
    PORT
      LAYER M4 ;
        RECT  0.054 34.032 0.138 34.056 ;
    END
  END wupper[13]
  PIN wupper[14]
    DIRECTION INPUT ;
    USE SIGNAL ;
    PORT
      LAYER M4 ;
        RECT  0.054 34.224 0.138 34.248 ;
    END
  END wupper[14]
  PIN wupper[15]
    DIRECTION INPUT ;
    USE SIGNAL ;
    PORT
      LAYER M4 ;
        RECT  0.054 34.416 0.138 34.44 ;
    END
  END wupper[15]
  PIN wupper[16]
    DIRECTION INPUT ;
    USE SIGNAL ;
    PORT
      LAYER M4 ;
        RECT  0.054 34.608 0.138 34.632 ;
    END
  END wupper[16]
  PIN wupper[17]
    DIRECTION INPUT ;
    USE SIGNAL ;
    PORT
      LAYER M4 ;
        RECT  0.054 34.848 0.138 34.872 ;
    END
  END wupper[17]
  PIN wupper[18]
    DIRECTION INPUT ;
    USE SIGNAL ;
    PORT
      LAYER M4 ;
        RECT  0.054 35.04 0.138 35.064 ;
    END
  END wupper[18]
  PIN wupper[19]
    DIRECTION INPUT ;
    USE SIGNAL ;
    PORT
      LAYER M4 ;
        RECT  0.054 35.232 0.138 35.256 ;
    END
  END wupper[19]
  PIN wupper[1]
    DIRECTION INPUT ;
    USE SIGNAL ;
    PORT
      LAYER M4 ;
        RECT  0.054 31.584 0.138 31.608 ;
    END
  END wupper[1]
  PIN wupper[20]
    DIRECTION INPUT ;
    USE SIGNAL ;
    PORT
      LAYER M4 ;
        RECT  0.054 35.424 0.138 35.448 ;
    END
  END wupper[20]
  PIN wupper[21]
    DIRECTION INPUT ;
    USE SIGNAL ;
    PORT
      LAYER M4 ;
        RECT  0.054 35.616 0.138 35.64 ;
    END
  END wupper[21]
  PIN wupper[22]
    DIRECTION INPUT ;
    USE SIGNAL ;
    PORT
      LAYER M4 ;
        RECT  0.054 35.856 0.138 35.88 ;
    END
  END wupper[22]
  PIN wupper[23]
    DIRECTION INPUT ;
    USE SIGNAL ;
    PORT
      LAYER M4 ;
        RECT  0.054 36.048 0.138 36.072 ;
    END
  END wupper[23]
  PIN wupper[24]
    DIRECTION INPUT ;
    USE SIGNAL ;
    PORT
      LAYER M4 ;
        RECT  0.054 36.24 0.138 36.264 ;
    END
  END wupper[24]
  PIN wupper[25]
    DIRECTION INPUT ;
    USE SIGNAL ;
    PORT
      LAYER M4 ;
        RECT  0.054 36.432 0.138 36.456 ;
    END
  END wupper[25]
  PIN wupper[26]
    DIRECTION INPUT ;
    USE SIGNAL ;
    PORT
      LAYER M4 ;
        RECT  0.054 36.672 0.138 36.696 ;
    END
  END wupper[26]
  PIN wupper[27]
    DIRECTION INPUT ;
    USE SIGNAL ;
    PORT
      LAYER M4 ;
        RECT  0.054 36.864 0.138 36.888 ;
    END
  END wupper[27]
  PIN wupper[28]
    DIRECTION INPUT ;
    USE SIGNAL ;
    PORT
      LAYER M4 ;
        RECT  0.054 37.056 0.138 37.08 ;
    END
  END wupper[28]
  PIN wupper[29]
    DIRECTION INPUT ;
    USE SIGNAL ;
    PORT
      LAYER M4 ;
        RECT  0.054 37.248 0.138 37.272 ;
    END
  END wupper[29]
  PIN wupper[2]
    DIRECTION INPUT ;
    USE SIGNAL ;
    PORT
      LAYER M4 ;
        RECT  0.054 31.776 0.138 31.8 ;
    END
  END wupper[2]
  PIN wupper[30]
    DIRECTION INPUT ;
    USE SIGNAL ;
    PORT
      LAYER M4 ;
        RECT  0.054 37.44 0.138 37.464 ;
    END
  END wupper[30]
  PIN wupper[31]
    DIRECTION INPUT ;
    USE SIGNAL ;
    PORT
      LAYER M4 ;
        RECT  0.054 37.68 0.138 37.704 ;
    END
  END wupper[31]
  PIN wupper[32]
    DIRECTION INPUT ;
    USE SIGNAL ;
    PORT
      LAYER M4 ;
        RECT  0.054 37.872 0.138 37.896 ;
    END
  END wupper[32]
  PIN wupper[33]
    DIRECTION INPUT ;
    USE SIGNAL ;
    PORT
      LAYER M4 ;
        RECT  0.054 38.064 0.138 38.088 ;
    END
  END wupper[33]
  PIN wupper[34]
    DIRECTION INPUT ;
    USE SIGNAL ;
    PORT
      LAYER M4 ;
        RECT  0.054 38.256 0.138 38.28 ;
    END
  END wupper[34]
  PIN wupper[35]
    DIRECTION INPUT ;
    USE SIGNAL ;
    PORT
      LAYER M4 ;
        RECT  0.054 38.496 0.138 38.52 ;
    END
  END wupper[35]
  PIN wupper[36]
    DIRECTION INPUT ;
    USE SIGNAL ;
    PORT
      LAYER M4 ;
        RECT  0.054 38.688 0.138 38.712 ;
    END
  END wupper[36]
  PIN wupper[37]
    DIRECTION INPUT ;
    USE SIGNAL ;
    PORT
      LAYER M4 ;
        RECT  0.054 38.88 0.138 38.904 ;
    END
  END wupper[37]
  PIN wupper[38]
    DIRECTION INPUT ;
    USE SIGNAL ;
    PORT
      LAYER M4 ;
        RECT  0.054 39.072 0.138 39.096 ;
    END
  END wupper[38]
  PIN wupper[39]
    DIRECTION INPUT ;
    USE SIGNAL ;
    PORT
      LAYER M4 ;
        RECT  0.054 39.312 0.138 39.336 ;
    END
  END wupper[39]
  PIN wupper[3]
    DIRECTION INPUT ;
    USE SIGNAL ;
    PORT
      LAYER M4 ;
        RECT  0.054 31.968 0.138 31.992 ;
    END
  END wupper[3]
  PIN wupper[40]
    DIRECTION INPUT ;
    USE SIGNAL ;
    PORT
      LAYER M4 ;
        RECT  0.054 39.504 0.138 39.528 ;
    END
  END wupper[40]
  PIN wupper[41]
    DIRECTION INPUT ;
    USE SIGNAL ;
    PORT
      LAYER M4 ;
        RECT  0.054 39.696 0.138 39.72 ;
    END
  END wupper[41]
  PIN wupper[42]
    DIRECTION INPUT ;
    USE SIGNAL ;
    PORT
      LAYER M4 ;
        RECT  0.054 39.888 0.138 39.912 ;
    END
  END wupper[42]
  PIN wupper[43]
    DIRECTION INPUT ;
    USE SIGNAL ;
    PORT
      LAYER M4 ;
        RECT  0.054 40.08 0.138 40.104 ;
    END
  END wupper[43]
  PIN wupper[44]
    DIRECTION INPUT ;
    USE SIGNAL ;
    PORT
      LAYER M4 ;
        RECT  0.054 40.32 0.138 40.344 ;
    END
  END wupper[44]
  PIN wupper[45]
    DIRECTION INPUT ;
    USE SIGNAL ;
    PORT
      LAYER M4 ;
        RECT  0.054 40.512 0.138 40.536 ;
    END
  END wupper[45]
  PIN wupper[46]
    DIRECTION INPUT ;
    USE SIGNAL ;
    PORT
      LAYER M4 ;
        RECT  0.054 40.704 0.138 40.728 ;
    END
  END wupper[46]
  PIN wupper[47]
    DIRECTION INPUT ;
    USE SIGNAL ;
    PORT
      LAYER M4 ;
        RECT  0.054 40.896 0.138 40.92 ;
    END
  END wupper[47]
  PIN wupper[48]
    DIRECTION INPUT ;
    USE SIGNAL ;
    PORT
      LAYER M4 ;
        RECT  0.054 41.136 0.138 41.16 ;
    END
  END wupper[48]
  PIN wupper[49]
    DIRECTION INPUT ;
    USE SIGNAL ;
    PORT
      LAYER M4 ;
        RECT  0.054 41.328 0.138 41.352 ;
    END
  END wupper[49]
  PIN wupper[4]
    DIRECTION INPUT ;
    USE SIGNAL ;
    PORT
      LAYER M4 ;
        RECT  0.054 32.208 0.138 32.232 ;
    END
  END wupper[4]
  PIN wupper[50]
    DIRECTION INPUT ;
    USE SIGNAL ;
    PORT
      LAYER M4 ;
        RECT  0.054 41.52 0.138 41.544 ;
    END
  END wupper[50]
  PIN wupper[51]
    DIRECTION INPUT ;
    USE SIGNAL ;
    PORT
      LAYER M4 ;
        RECT  0.054 41.712 0.138 41.736 ;
    END
  END wupper[51]
  PIN wupper[52]
    DIRECTION INPUT ;
    USE SIGNAL ;
    PORT
      LAYER M4 ;
        RECT  0.054 41.952 0.138 41.976 ;
    END
  END wupper[52]
  PIN wupper[53]
    DIRECTION INPUT ;
    USE SIGNAL ;
    PORT
      LAYER M4 ;
        RECT  0.054 42.144 0.138 42.168 ;
    END
  END wupper[53]
  PIN wupper[54]
    DIRECTION INPUT ;
    USE SIGNAL ;
    PORT
      LAYER M4 ;
        RECT  0.054 42.336 0.138 42.36 ;
    END
  END wupper[54]
  PIN wupper[55]
    DIRECTION INPUT ;
    USE SIGNAL ;
    PORT
      LAYER M4 ;
        RECT  0.054 42.528 0.138 42.552 ;
    END
  END wupper[55]
  PIN wupper[56]
    DIRECTION INPUT ;
    USE SIGNAL ;
    PORT
      LAYER M4 ;
        RECT  0.054 42.72 0.138 42.744 ;
    END
  END wupper[56]
  PIN wupper[57]
    DIRECTION INPUT ;
    USE SIGNAL ;
    PORT
      LAYER M4 ;
        RECT  0.054 42.96 0.138 42.984 ;
    END
  END wupper[57]
  PIN wupper[58]
    DIRECTION INPUT ;
    USE SIGNAL ;
    PORT
      LAYER M4 ;
        RECT  0.054 43.152 0.138 43.176 ;
    END
  END wupper[58]
  PIN wupper[59]
    DIRECTION INPUT ;
    USE SIGNAL ;
    PORT
      LAYER M4 ;
        RECT  0.054 43.344 0.138 43.368 ;
    END
  END wupper[59]
  PIN wupper[5]
    DIRECTION INPUT ;
    USE SIGNAL ;
    PORT
      LAYER M4 ;
        RECT  0.054 32.4 0.138 32.424 ;
    END
  END wupper[5]
  PIN wupper[60]
    DIRECTION INPUT ;
    USE SIGNAL ;
    PORT
      LAYER M4 ;
        RECT  0.054 43.536 0.138 43.56 ;
    END
  END wupper[60]
  PIN wupper[61]
    DIRECTION INPUT ;
    USE SIGNAL ;
    PORT
      LAYER M4 ;
        RECT  0.054 43.776 0.138 43.8 ;
    END
  END wupper[61]
  PIN wupper[62]
    DIRECTION INPUT ;
    USE SIGNAL ;
    PORT
      LAYER M4 ;
        RECT  0.054 43.968 0.138 43.992 ;
    END
  END wupper[62]
  PIN wupper[63]
    DIRECTION INPUT ;
    USE SIGNAL ;
    PORT
      LAYER M4 ;
        RECT  0.054 44.16 0.138 44.184 ;
    END
  END wupper[63]
  PIN wupper[64]
    DIRECTION INPUT ;
    USE SIGNAL ;
    PORT
      LAYER M4 ;
        RECT  0.054 44.352 0.138 44.376 ;
    END
  END wupper[64]
  PIN wupper[65]
    DIRECTION INPUT ;
    USE SIGNAL ;
    PORT
      LAYER M4 ;
        RECT  0.054 44.592 0.138 44.616 ;
    END
  END wupper[65]
  PIN wupper[66]
    DIRECTION INPUT ;
    USE SIGNAL ;
    PORT
      LAYER M4 ;
        RECT  0.054 44.784 0.138 44.808 ;
    END
  END wupper[66]
  PIN wupper[67]
    DIRECTION INPUT ;
    USE SIGNAL ;
    PORT
      LAYER M4 ;
        RECT  0.054 44.976 0.138 45 ;
    END
  END wupper[67]
  PIN wupper[68]
    DIRECTION INPUT ;
    USE SIGNAL ;
    PORT
      LAYER M4 ;
        RECT  0.054 45.168 0.138 45.192 ;
    END
  END wupper[68]
  PIN wupper[69]
    DIRECTION INPUT ;
    USE SIGNAL ;
    PORT
      LAYER M4 ;
        RECT  0.054 45.36 0.138 45.384 ;
    END
  END wupper[69]
  PIN wupper[6]
    DIRECTION INPUT ;
    USE SIGNAL ;
    PORT
      LAYER M4 ;
        RECT  0.054 32.592 0.138 32.616 ;
    END
  END wupper[6]
  PIN wupper[70]
    DIRECTION INPUT ;
    USE SIGNAL ;
    PORT
      LAYER M4 ;
        RECT  0.054 45.6 0.138 45.624 ;
    END
  END wupper[70]
  PIN wupper[71]
    DIRECTION INPUT ;
    USE SIGNAL ;
    PORT
      LAYER M4 ;
        RECT  0.054 45.792 0.138 45.816 ;
    END
  END wupper[71]
  PIN wupper[72]
    DIRECTION INPUT ;
    USE SIGNAL ;
    PORT
      LAYER M4 ;
        RECT  0.054 45.984 0.138 46.008 ;
    END
  END wupper[72]
  PIN wupper[73]
    DIRECTION INPUT ;
    USE SIGNAL ;
    PORT
      LAYER M4 ;
        RECT  0.054 46.176 0.138 46.2 ;
    END
  END wupper[73]
  PIN wupper[74]
    DIRECTION INPUT ;
    USE SIGNAL ;
    PORT
      LAYER M4 ;
        RECT  0.054 46.416 0.138 46.44 ;
    END
  END wupper[74]
  PIN wupper[75]
    DIRECTION INPUT ;
    USE SIGNAL ;
    PORT
      LAYER M4 ;
        RECT  0.054 46.608 0.138 46.632 ;
    END
  END wupper[75]
  PIN wupper[76]
    DIRECTION INPUT ;
    USE SIGNAL ;
    PORT
      LAYER M4 ;
        RECT  0.054 46.8 0.138 46.824 ;
    END
  END wupper[76]
  PIN wupper[77]
    DIRECTION INPUT ;
    USE SIGNAL ;
    PORT
      LAYER M4 ;
        RECT  0.054 46.992 0.138 47.016 ;
    END
  END wupper[77]
  PIN wupper[78]
    DIRECTION INPUT ;
    USE SIGNAL ;
    PORT
      LAYER M4 ;
        RECT  0.054 47.184 0.138 47.208 ;
    END
  END wupper[78]
  PIN wupper[79]
    DIRECTION INPUT ;
    USE SIGNAL ;
    PORT
      LAYER M4 ;
        RECT  0.054 47.424 0.138 47.448 ;
    END
  END wupper[79]
  PIN wupper[7]
    DIRECTION INPUT ;
    USE SIGNAL ;
    PORT
      LAYER M4 ;
        RECT  0.054 32.784 0.138 32.808 ;
    END
  END wupper[7]
  PIN wupper[80]
    DIRECTION INPUT ;
    USE SIGNAL ;
    PORT
      LAYER M4 ;
        RECT  0.054 47.616 0.138 47.64 ;
    END
  END wupper[80]
  PIN wupper[81]
    DIRECTION INPUT ;
    USE SIGNAL ;
    PORT
      LAYER M4 ;
        RECT  0.054 47.808 0.138 47.832 ;
    END
  END wupper[81]
  PIN wupper[82]
    DIRECTION INPUT ;
    USE SIGNAL ;
    PORT
      LAYER M4 ;
        RECT  0.054 48 0.138 48.024 ;
    END
  END wupper[82]
  PIN wupper[83]
    DIRECTION INPUT ;
    USE SIGNAL ;
    PORT
      LAYER M4 ;
        RECT  0.054 48.24 0.138 48.264 ;
    END
  END wupper[83]
  PIN wupper[84]
    DIRECTION INPUT ;
    USE SIGNAL ;
    PORT
      LAYER M4 ;
        RECT  0.054 48.432 0.138 48.456 ;
    END
  END wupper[84]
  PIN wupper[85]
    DIRECTION INPUT ;
    USE SIGNAL ;
    PORT
      LAYER M4 ;
        RECT  0.054 48.624 0.138 48.648 ;
    END
  END wupper[85]
  PIN wupper[86]
    DIRECTION INPUT ;
    USE SIGNAL ;
    PORT
      LAYER M4 ;
        RECT  0.054 48.816 0.138 48.84 ;
    END
  END wupper[86]
  PIN wupper[87]
    DIRECTION INPUT ;
    USE SIGNAL ;
    PORT
      LAYER M4 ;
        RECT  0.054 49.056 0.138 49.08 ;
    END
  END wupper[87]
  PIN wupper[88]
    DIRECTION INPUT ;
    USE SIGNAL ;
    PORT
      LAYER M4 ;
        RECT  0.054 49.248 0.138 49.272 ;
    END
  END wupper[88]
  PIN wupper[89]
    DIRECTION INPUT ;
    USE SIGNAL ;
    PORT
      LAYER M4 ;
        RECT  0.054 49.44 0.138 49.464 ;
    END
  END wupper[89]
  PIN wupper[8]
    DIRECTION INPUT ;
    USE SIGNAL ;
    PORT
      LAYER M4 ;
        RECT  0.054 32.976 0.138 33 ;
    END
  END wupper[8]
  PIN wupper[90]
    DIRECTION INPUT ;
    USE SIGNAL ;
    PORT
      LAYER M4 ;
        RECT  0.054 49.632 0.138 49.656 ;
    END
  END wupper[90]
  PIN wupper[91]
    DIRECTION INPUT ;
    USE SIGNAL ;
    PORT
      LAYER M4 ;
        RECT  0.054 49.824 0.138 49.848 ;
    END
  END wupper[91]
  PIN wupper[92]
    DIRECTION INPUT ;
    USE SIGNAL ;
    PORT
      LAYER M4 ;
        RECT  0.054 50.064 0.138 50.088 ;
    END
  END wupper[92]
  PIN wupper[93]
    DIRECTION INPUT ;
    USE SIGNAL ;
    PORT
      LAYER M4 ;
        RECT  0.054 50.256 0.138 50.28 ;
    END
  END wupper[93]
  PIN wupper[94]
    DIRECTION INPUT ;
    USE SIGNAL ;
    PORT
      LAYER M4 ;
        RECT  0.054 50.448 0.138 50.472 ;
    END
  END wupper[94]
  PIN wupper[95]
    DIRECTION INPUT ;
    USE SIGNAL ;
    PORT
      LAYER M4 ;
        RECT  0.054 50.64 0.138 50.664 ;
    END
  END wupper[95]
  PIN wupper[96]
    DIRECTION INPUT ;
    USE SIGNAL ;
    PORT
      LAYER M4 ;
        RECT  0.054 50.88 0.138 50.904 ;
    END
  END wupper[96]
  PIN wupper[97]
    DIRECTION INPUT ;
    USE SIGNAL ;
    PORT
      LAYER M4 ;
        RECT  0.054 51.072 0.138 51.096 ;
    END
  END wupper[97]
  PIN wupper[98]
    DIRECTION INPUT ;
    USE SIGNAL ;
    PORT
      LAYER M4 ;
        RECT  0.054 51.264 0.138 51.288 ;
    END
  END wupper[98]
  PIN wupper[99]
    DIRECTION INPUT ;
    USE SIGNAL ;
    PORT
      LAYER M4 ;
        RECT  0.054 51.456 0.138 51.48 ;
    END
  END wupper[99]
  PIN wupper[9]
    DIRECTION INPUT ;
    USE SIGNAL ;
    PORT
      LAYER M4 ;
        RECT  0.054 33.216 0.138 33.24 ;
    END
  END wupper[9]
  PIN x[0]
    DIRECTION INPUT ;
    USE SIGNAL ;
    PORT
      LAYER M4 ;
        RECT  0.054 5.424 0.138 5.448 ;
    END
  END x[0]
  PIN x[100]
    DIRECTION INPUT ;
    USE SIGNAL ;
    PORT
      LAYER M4 ;
        RECT  0.054 25.68 0.138 25.704 ;
    END
  END x[100]
  PIN x[101]
    DIRECTION INPUT ;
    USE SIGNAL ;
    PORT
      LAYER M4 ;
        RECT  0.054 25.872 0.138 25.896 ;
    END
  END x[101]
  PIN x[102]
    DIRECTION INPUT ;
    USE SIGNAL ;
    PORT
      LAYER M4 ;
        RECT  0.054 26.112 0.138 26.136 ;
    END
  END x[102]
  PIN x[103]
    DIRECTION INPUT ;
    USE SIGNAL ;
    PORT
      LAYER M4 ;
        RECT  0.054 26.304 0.138 26.328 ;
    END
  END x[103]
  PIN x[104]
    DIRECTION INPUT ;
    USE SIGNAL ;
    PORT
      LAYER M4 ;
        RECT  0.054 26.496 0.138 26.52 ;
    END
  END x[104]
  PIN x[105]
    DIRECTION INPUT ;
    USE SIGNAL ;
    PORT
      LAYER M4 ;
        RECT  0.054 26.688 0.138 26.712 ;
    END
  END x[105]
  PIN x[106]
    DIRECTION INPUT ;
    USE SIGNAL ;
    PORT
      LAYER M4 ;
        RECT  0.054 26.928 0.138 26.952 ;
    END
  END x[106]
  PIN x[107]
    DIRECTION INPUT ;
    USE SIGNAL ;
    PORT
      LAYER M4 ;
        RECT  0.054 27.12 0.138 27.144 ;
    END
  END x[107]
  PIN x[108]
    DIRECTION INPUT ;
    USE SIGNAL ;
    PORT
      LAYER M4 ;
        RECT  0.054 27.312 0.138 27.336 ;
    END
  END x[108]
  PIN x[109]
    DIRECTION INPUT ;
    USE SIGNAL ;
    PORT
      LAYER M4 ;
        RECT  0.054 27.504 0.138 27.528 ;
    END
  END x[109]
  PIN x[10]
    DIRECTION INPUT ;
    USE SIGNAL ;
    PORT
      LAYER M4 ;
        RECT  0.054 7.44 0.138 7.464 ;
    END
  END x[10]
  PIN x[110]
    DIRECTION INPUT ;
    USE SIGNAL ;
    PORT
      LAYER M4 ;
        RECT  0.054 27.696 0.138 27.72 ;
    END
  END x[110]
  PIN x[111]
    DIRECTION INPUT ;
    USE SIGNAL ;
    PORT
      LAYER M4 ;
        RECT  0.054 27.936 0.138 27.96 ;
    END
  END x[111]
  PIN x[112]
    DIRECTION INPUT ;
    USE SIGNAL ;
    PORT
      LAYER M4 ;
        RECT  0.054 28.128 0.138 28.152 ;
    END
  END x[112]
  PIN x[113]
    DIRECTION INPUT ;
    USE SIGNAL ;
    PORT
      LAYER M4 ;
        RECT  0.054 28.32 0.138 28.344 ;
    END
  END x[113]
  PIN x[114]
    DIRECTION INPUT ;
    USE SIGNAL ;
    PORT
      LAYER M4 ;
        RECT  0.054 28.512 0.138 28.536 ;
    END
  END x[114]
  PIN x[115]
    DIRECTION INPUT ;
    USE SIGNAL ;
    PORT
      LAYER M4 ;
        RECT  0.054 28.752 0.138 28.776 ;
    END
  END x[115]
  PIN x[116]
    DIRECTION INPUT ;
    USE SIGNAL ;
    PORT
      LAYER M4 ;
        RECT  0.054 28.944 0.138 28.968 ;
    END
  END x[116]
  PIN x[117]
    DIRECTION INPUT ;
    USE SIGNAL ;
    PORT
      LAYER M4 ;
        RECT  0.054 29.136 0.138 29.16 ;
    END
  END x[117]
  PIN x[118]
    DIRECTION INPUT ;
    USE SIGNAL ;
    PORT
      LAYER M4 ;
        RECT  0.054 29.328 0.138 29.352 ;
    END
  END x[118]
  PIN x[119]
    DIRECTION INPUT ;
    USE SIGNAL ;
    PORT
      LAYER M4 ;
        RECT  0.054 29.568 0.138 29.592 ;
    END
  END x[119]
  PIN x[11]
    DIRECTION INPUT ;
    USE SIGNAL ;
    PORT
      LAYER M4 ;
        RECT  0.054 7.632 0.138 7.656 ;
    END
  END x[11]
  PIN x[120]
    DIRECTION INPUT ;
    USE SIGNAL ;
    PORT
      LAYER M4 ;
        RECT  0.054 29.76 0.138 29.784 ;
    END
  END x[120]
  PIN x[121]
    DIRECTION INPUT ;
    USE SIGNAL ;
    PORT
      LAYER M4 ;
        RECT  0.054 29.952 0.138 29.976 ;
    END
  END x[121]
  PIN x[122]
    DIRECTION INPUT ;
    USE SIGNAL ;
    PORT
      LAYER M4 ;
        RECT  0.054 30.144 0.138 30.168 ;
    END
  END x[122]
  PIN x[123]
    DIRECTION INPUT ;
    USE SIGNAL ;
    PORT
      LAYER M4 ;
        RECT  0.054 30.336 0.138 30.36 ;
    END
  END x[123]
  PIN x[124]
    DIRECTION INPUT ;
    USE SIGNAL ;
    PORT
      LAYER M4 ;
        RECT  0.054 30.576 0.138 30.6 ;
    END
  END x[124]
  PIN x[125]
    DIRECTION INPUT ;
    USE SIGNAL ;
    PORT
      LAYER M4 ;
        RECT  0.054 30.768 0.138 30.792 ;
    END
  END x[125]
  PIN x[126]
    DIRECTION INPUT ;
    USE SIGNAL ;
    PORT
      LAYER M4 ;
        RECT  0.054 30.96 0.138 30.984 ;
    END
  END x[126]
  PIN x[127]
    DIRECTION INPUT ;
    USE SIGNAL ;
    PORT
      LAYER M4 ;
        RECT  0.054 31.152 0.138 31.176 ;
    END
  END x[127]
  PIN x[12]
    DIRECTION INPUT ;
    USE SIGNAL ;
    PORT
      LAYER M4 ;
        RECT  0.054 7.824 0.138 7.848 ;
    END
  END x[12]
  PIN x[13]
    DIRECTION INPUT ;
    USE SIGNAL ;
    PORT
      LAYER M4 ;
        RECT  0.054 8.016 0.138 8.04 ;
    END
  END x[13]
  PIN x[14]
    DIRECTION INPUT ;
    USE SIGNAL ;
    PORT
      LAYER M4 ;
        RECT  0.054 8.208 0.138 8.232 ;
    END
  END x[14]
  PIN x[15]
    DIRECTION INPUT ;
    USE SIGNAL ;
    PORT
      LAYER M4 ;
        RECT  0.054 8.448 0.138 8.472 ;
    END
  END x[15]
  PIN x[16]
    DIRECTION INPUT ;
    USE SIGNAL ;
    PORT
      LAYER M4 ;
        RECT  0.054 8.64 0.138 8.664 ;
    END
  END x[16]
  PIN x[17]
    DIRECTION INPUT ;
    USE SIGNAL ;
    PORT
      LAYER M4 ;
        RECT  0.054 8.832 0.138 8.856 ;
    END
  END x[17]
  PIN x[18]
    DIRECTION INPUT ;
    USE SIGNAL ;
    PORT
      LAYER M4 ;
        RECT  0.054 9.024 0.138 9.048 ;
    END
  END x[18]
  PIN x[19]
    DIRECTION INPUT ;
    USE SIGNAL ;
    PORT
      LAYER M4 ;
        RECT  0.054 9.264 0.138 9.288 ;
    END
  END x[19]
  PIN x[1]
    DIRECTION INPUT ;
    USE SIGNAL ;
    PORT
      LAYER M4 ;
        RECT  0.054 5.568 0.138 5.592 ;
    END
  END x[1]
  PIN x[20]
    DIRECTION INPUT ;
    USE SIGNAL ;
    PORT
      LAYER M4 ;
        RECT  0.054 9.456 0.138 9.48 ;
    END
  END x[20]
  PIN x[21]
    DIRECTION INPUT ;
    USE SIGNAL ;
    PORT
      LAYER M4 ;
        RECT  0.054 9.648 0.138 9.672 ;
    END
  END x[21]
  PIN x[22]
    DIRECTION INPUT ;
    USE SIGNAL ;
    PORT
      LAYER M4 ;
        RECT  0.054 9.84 0.138 9.864 ;
    END
  END x[22]
  PIN x[23]
    DIRECTION INPUT ;
    USE SIGNAL ;
    PORT
      LAYER M4 ;
        RECT  0.054 10.08 0.138 10.104 ;
    END
  END x[23]
  PIN x[24]
    DIRECTION INPUT ;
    USE SIGNAL ;
    PORT
      LAYER M4 ;
        RECT  0.054 10.272 0.138 10.296 ;
    END
  END x[24]
  PIN x[25]
    DIRECTION INPUT ;
    USE SIGNAL ;
    PORT
      LAYER M4 ;
        RECT  0.054 10.464 0.138 10.488 ;
    END
  END x[25]
  PIN x[26]
    DIRECTION INPUT ;
    USE SIGNAL ;
    PORT
      LAYER M4 ;
        RECT  0.054 10.656 0.138 10.68 ;
    END
  END x[26]
  PIN x[27]
    DIRECTION INPUT ;
    USE SIGNAL ;
    PORT
      LAYER M4 ;
        RECT  0.054 10.848 0.138 10.872 ;
    END
  END x[27]
  PIN x[28]
    DIRECTION INPUT ;
    USE SIGNAL ;
    PORT
      LAYER M4 ;
        RECT  0.054 11.088 0.138 11.112 ;
    END
  END x[28]
  PIN x[29]
    DIRECTION INPUT ;
    USE SIGNAL ;
    PORT
      LAYER M4 ;
        RECT  0.054 11.28 0.138 11.304 ;
    END
  END x[29]
  PIN x[2]
    DIRECTION INPUT ;
    USE SIGNAL ;
    PORT
      LAYER M4 ;
        RECT  0.054 5.808 0.138 5.832 ;
    END
  END x[2]
  PIN x[30]
    DIRECTION INPUT ;
    USE SIGNAL ;
    PORT
      LAYER M4 ;
        RECT  0.054 11.472 0.138 11.496 ;
    END
  END x[30]
  PIN x[31]
    DIRECTION INPUT ;
    USE SIGNAL ;
    PORT
      LAYER M4 ;
        RECT  0.054 11.664 0.138 11.688 ;
    END
  END x[31]
  PIN x[32]
    DIRECTION INPUT ;
    USE SIGNAL ;
    PORT
      LAYER M4 ;
        RECT  0.054 11.904 0.138 11.928 ;
    END
  END x[32]
  PIN x[33]
    DIRECTION INPUT ;
    USE SIGNAL ;
    PORT
      LAYER M4 ;
        RECT  0.054 12.096 0.138 12.12 ;
    END
  END x[33]
  PIN x[34]
    DIRECTION INPUT ;
    USE SIGNAL ;
    PORT
      LAYER M4 ;
        RECT  0.054 12.288 0.138 12.312 ;
    END
  END x[34]
  PIN x[35]
    DIRECTION INPUT ;
    USE SIGNAL ;
    PORT
      LAYER M4 ;
        RECT  0.054 12.48 0.138 12.504 ;
    END
  END x[35]
  PIN x[36]
    DIRECTION INPUT ;
    USE SIGNAL ;
    PORT
      LAYER M4 ;
        RECT  0.054 12.72 0.138 12.744 ;
    END
  END x[36]
  PIN x[37]
    DIRECTION INPUT ;
    USE SIGNAL ;
    PORT
      LAYER M4 ;
        RECT  0.054 12.912 0.138 12.936 ;
    END
  END x[37]
  PIN x[38]
    DIRECTION INPUT ;
    USE SIGNAL ;
    PORT
      LAYER M4 ;
        RECT  0.054 13.104 0.138 13.128 ;
    END
  END x[38]
  PIN x[39]
    DIRECTION INPUT ;
    USE SIGNAL ;
    PORT
      LAYER M4 ;
        RECT  0.054 13.296 0.138 13.32 ;
    END
  END x[39]
  PIN x[3]
    DIRECTION INPUT ;
    USE SIGNAL ;
    PORT
      LAYER M4 ;
        RECT  0.054 6 0.138 6.024 ;
    END
  END x[3]
  PIN x[40]
    DIRECTION INPUT ;
    USE SIGNAL ;
    PORT
      LAYER M4 ;
        RECT  0.054 13.488 0.138 13.512 ;
    END
  END x[40]
  PIN x[41]
    DIRECTION INPUT ;
    USE SIGNAL ;
    PORT
      LAYER M4 ;
        RECT  0.054 13.728 0.138 13.752 ;
    END
  END x[41]
  PIN x[42]
    DIRECTION INPUT ;
    USE SIGNAL ;
    PORT
      LAYER M4 ;
        RECT  0.054 13.92 0.138 13.944 ;
    END
  END x[42]
  PIN x[43]
    DIRECTION INPUT ;
    USE SIGNAL ;
    PORT
      LAYER M4 ;
        RECT  0.054 14.112 0.138 14.136 ;
    END
  END x[43]
  PIN x[44]
    DIRECTION INPUT ;
    USE SIGNAL ;
    PORT
      LAYER M4 ;
        RECT  0.054 14.304 0.138 14.328 ;
    END
  END x[44]
  PIN x[45]
    DIRECTION INPUT ;
    USE SIGNAL ;
    PORT
      LAYER M4 ;
        RECT  0.054 14.544 0.138 14.568 ;
    END
  END x[45]
  PIN x[46]
    DIRECTION INPUT ;
    USE SIGNAL ;
    PORT
      LAYER M4 ;
        RECT  0.054 14.736 0.138 14.76 ;
    END
  END x[46]
  PIN x[47]
    DIRECTION INPUT ;
    USE SIGNAL ;
    PORT
      LAYER M4 ;
        RECT  0.054 14.928 0.138 14.952 ;
    END
  END x[47]
  PIN x[48]
    DIRECTION INPUT ;
    USE SIGNAL ;
    PORT
      LAYER M4 ;
        RECT  0.054 15.12 0.138 15.144 ;
    END
  END x[48]
  PIN x[49]
    DIRECTION INPUT ;
    USE SIGNAL ;
    PORT
      LAYER M4 ;
        RECT  0.054 15.312 0.138 15.336 ;
    END
  END x[49]
  PIN x[4]
    DIRECTION INPUT ;
    USE SIGNAL ;
    PORT
      LAYER M4 ;
        RECT  0.054 6.192 0.138 6.216 ;
    END
  END x[4]
  PIN x[50]
    DIRECTION INPUT ;
    USE SIGNAL ;
    PORT
      LAYER M4 ;
        RECT  0.054 15.552 0.138 15.576 ;
    END
  END x[50]
  PIN x[51]
    DIRECTION INPUT ;
    USE SIGNAL ;
    PORT
      LAYER M4 ;
        RECT  0.054 15.744 0.138 15.768 ;
    END
  END x[51]
  PIN x[52]
    DIRECTION INPUT ;
    USE SIGNAL ;
    PORT
      LAYER M4 ;
        RECT  0.054 15.936 0.138 15.96 ;
    END
  END x[52]
  PIN x[53]
    DIRECTION INPUT ;
    USE SIGNAL ;
    PORT
      LAYER M4 ;
        RECT  0.054 16.128 0.138 16.152 ;
    END
  END x[53]
  PIN x[54]
    DIRECTION INPUT ;
    USE SIGNAL ;
    PORT
      LAYER M4 ;
        RECT  0.054 16.368 0.138 16.392 ;
    END
  END x[54]
  PIN x[55]
    DIRECTION INPUT ;
    USE SIGNAL ;
    PORT
      LAYER M4 ;
        RECT  0.054 16.56 0.138 16.584 ;
    END
  END x[55]
  PIN x[56]
    DIRECTION INPUT ;
    USE SIGNAL ;
    PORT
      LAYER M4 ;
        RECT  0.054 16.752 0.138 16.776 ;
    END
  END x[56]
  PIN x[57]
    DIRECTION INPUT ;
    USE SIGNAL ;
    PORT
      LAYER M4 ;
        RECT  0.054 16.944 0.138 16.968 ;
    END
  END x[57]
  PIN x[58]
    DIRECTION INPUT ;
    USE SIGNAL ;
    PORT
      LAYER M4 ;
        RECT  0.054 17.184 0.138 17.208 ;
    END
  END x[58]
  PIN x[59]
    DIRECTION INPUT ;
    USE SIGNAL ;
    PORT
      LAYER M4 ;
        RECT  0.054 17.376 0.138 17.4 ;
    END
  END x[59]
  PIN x[5]
    DIRECTION INPUT ;
    USE SIGNAL ;
    PORT
      LAYER M4 ;
        RECT  0.054 6.384 0.138 6.408 ;
    END
  END x[5]
  PIN x[60]
    DIRECTION INPUT ;
    USE SIGNAL ;
    PORT
      LAYER M4 ;
        RECT  0.054 17.568 0.138 17.592 ;
    END
  END x[60]
  PIN x[61]
    DIRECTION INPUT ;
    USE SIGNAL ;
    PORT
      LAYER M4 ;
        RECT  0.054 17.76 0.138 17.784 ;
    END
  END x[61]
  PIN x[62]
    DIRECTION INPUT ;
    USE SIGNAL ;
    PORT
      LAYER M4 ;
        RECT  0.054 17.952 0.138 17.976 ;
    END
  END x[62]
  PIN x[63]
    DIRECTION INPUT ;
    USE SIGNAL ;
    PORT
      LAYER M4 ;
        RECT  0.054 18.192 0.138 18.216 ;
    END
  END x[63]
  PIN x[64]
    DIRECTION INPUT ;
    USE SIGNAL ;
    PORT
      LAYER M4 ;
        RECT  0.054 18.384 0.138 18.408 ;
    END
  END x[64]
  PIN x[65]
    DIRECTION INPUT ;
    USE SIGNAL ;
    PORT
      LAYER M4 ;
        RECT  0.054 18.576 0.138 18.6 ;
    END
  END x[65]
  PIN x[66]
    DIRECTION INPUT ;
    USE SIGNAL ;
    PORT
      LAYER M4 ;
        RECT  0.054 18.768 0.138 18.792 ;
    END
  END x[66]
  PIN x[67]
    DIRECTION INPUT ;
    USE SIGNAL ;
    PORT
      LAYER M4 ;
        RECT  0.054 19.008 0.138 19.032 ;
    END
  END x[67]
  PIN x[68]
    DIRECTION INPUT ;
    USE SIGNAL ;
    PORT
      LAYER M4 ;
        RECT  0.054 19.2 0.138 19.224 ;
    END
  END x[68]
  PIN x[69]
    DIRECTION INPUT ;
    USE SIGNAL ;
    PORT
      LAYER M4 ;
        RECT  0.054 19.392 0.138 19.416 ;
    END
  END x[69]
  PIN x[6]
    DIRECTION INPUT ;
    USE SIGNAL ;
    PORT
      LAYER M4 ;
        RECT  0.054 6.624 0.138 6.648 ;
    END
  END x[6]
  PIN x[70]
    DIRECTION INPUT ;
    USE SIGNAL ;
    PORT
      LAYER M4 ;
        RECT  0.054 19.584 0.138 19.608 ;
    END
  END x[70]
  PIN x[71]
    DIRECTION INPUT ;
    USE SIGNAL ;
    PORT
      LAYER M4 ;
        RECT  0.054 19.824 0.138 19.848 ;
    END
  END x[71]
  PIN x[72]
    DIRECTION INPUT ;
    USE SIGNAL ;
    PORT
      LAYER M4 ;
        RECT  0.054 20.016 0.138 20.04 ;
    END
  END x[72]
  PIN x[73]
    DIRECTION INPUT ;
    USE SIGNAL ;
    PORT
      LAYER M4 ;
        RECT  0.054 20.208 0.138 20.232 ;
    END
  END x[73]
  PIN x[74]
    DIRECTION INPUT ;
    USE SIGNAL ;
    PORT
      LAYER M4 ;
        RECT  0.054 20.4 0.138 20.424 ;
    END
  END x[74]
  PIN x[75]
    DIRECTION INPUT ;
    USE SIGNAL ;
    PORT
      LAYER M4 ;
        RECT  0.054 20.592 0.138 20.616 ;
    END
  END x[75]
  PIN x[76]
    DIRECTION INPUT ;
    USE SIGNAL ;
    PORT
      LAYER M4 ;
        RECT  0.054 20.832 0.138 20.856 ;
    END
  END x[76]
  PIN x[77]
    DIRECTION INPUT ;
    USE SIGNAL ;
    PORT
      LAYER M4 ;
        RECT  0.054 21.024 0.138 21.048 ;
    END
  END x[77]
  PIN x[78]
    DIRECTION INPUT ;
    USE SIGNAL ;
    PORT
      LAYER M4 ;
        RECT  0.054 21.216 0.138 21.24 ;
    END
  END x[78]
  PIN x[79]
    DIRECTION INPUT ;
    USE SIGNAL ;
    PORT
      LAYER M4 ;
        RECT  0.054 21.408 0.138 21.432 ;
    END
  END x[79]
  PIN x[7]
    DIRECTION INPUT ;
    USE SIGNAL ;
    PORT
      LAYER M4 ;
        RECT  0.054 6.816 0.138 6.84 ;
    END
  END x[7]
  PIN x[80]
    DIRECTION INPUT ;
    USE SIGNAL ;
    PORT
      LAYER M4 ;
        RECT  0.054 21.648 0.138 21.672 ;
    END
  END x[80]
  PIN x[81]
    DIRECTION INPUT ;
    USE SIGNAL ;
    PORT
      LAYER M4 ;
        RECT  0.054 21.84 0.138 21.864 ;
    END
  END x[81]
  PIN x[82]
    DIRECTION INPUT ;
    USE SIGNAL ;
    PORT
      LAYER M4 ;
        RECT  0.054 22.032 0.138 22.056 ;
    END
  END x[82]
  PIN x[83]
    DIRECTION INPUT ;
    USE SIGNAL ;
    PORT
      LAYER M4 ;
        RECT  0.054 22.224 0.138 22.248 ;
    END
  END x[83]
  PIN x[84]
    DIRECTION INPUT ;
    USE SIGNAL ;
    PORT
      LAYER M4 ;
        RECT  0.054 22.464 0.138 22.488 ;
    END
  END x[84]
  PIN x[85]
    DIRECTION INPUT ;
    USE SIGNAL ;
    PORT
      LAYER M4 ;
        RECT  0.054 22.656 0.138 22.68 ;
    END
  END x[85]
  PIN x[86]
    DIRECTION INPUT ;
    USE SIGNAL ;
    PORT
      LAYER M4 ;
        RECT  0.054 22.848 0.138 22.872 ;
    END
  END x[86]
  PIN x[87]
    DIRECTION INPUT ;
    USE SIGNAL ;
    PORT
      LAYER M4 ;
        RECT  0.054 23.04 0.138 23.064 ;
    END
  END x[87]
  PIN x[88]
    DIRECTION INPUT ;
    USE SIGNAL ;
    PORT
      LAYER M4 ;
        RECT  0.054 23.232 0.138 23.256 ;
    END
  END x[88]
  PIN x[89]
    DIRECTION INPUT ;
    USE SIGNAL ;
    PORT
      LAYER M4 ;
        RECT  0.054 23.472 0.138 23.496 ;
    END
  END x[89]
  PIN x[8]
    DIRECTION INPUT ;
    USE SIGNAL ;
    PORT
      LAYER M4 ;
        RECT  0.054 7.008 0.138 7.032 ;
    END
  END x[8]
  PIN x[90]
    DIRECTION INPUT ;
    USE SIGNAL ;
    PORT
      LAYER M4 ;
        RECT  0.054 23.664 0.138 23.688 ;
    END
  END x[90]
  PIN x[91]
    DIRECTION INPUT ;
    USE SIGNAL ;
    PORT
      LAYER M4 ;
        RECT  0.054 23.856 0.138 23.88 ;
    END
  END x[91]
  PIN x[92]
    DIRECTION INPUT ;
    USE SIGNAL ;
    PORT
      LAYER M4 ;
        RECT  0.054 24.048 0.138 24.072 ;
    END
  END x[92]
  PIN x[93]
    DIRECTION INPUT ;
    USE SIGNAL ;
    PORT
      LAYER M4 ;
        RECT  0.054 24.288 0.138 24.312 ;
    END
  END x[93]
  PIN x[94]
    DIRECTION INPUT ;
    USE SIGNAL ;
    PORT
      LAYER M4 ;
        RECT  0.054 24.48 0.138 24.504 ;
    END
  END x[94]
  PIN x[95]
    DIRECTION INPUT ;
    USE SIGNAL ;
    PORT
      LAYER M4 ;
        RECT  0.054 24.672 0.138 24.696 ;
    END
  END x[95]
  PIN x[96]
    DIRECTION INPUT ;
    USE SIGNAL ;
    PORT
      LAYER M4 ;
        RECT  0.054 24.864 0.138 24.888 ;
    END
  END x[96]
  PIN x[97]
    DIRECTION INPUT ;
    USE SIGNAL ;
    PORT
      LAYER M4 ;
        RECT  0.054 25.056 0.138 25.08 ;
    END
  END x[97]
  PIN x[98]
    DIRECTION INPUT ;
    USE SIGNAL ;
    PORT
      LAYER M4 ;
        RECT  0.054 25.296 0.138 25.32 ;
    END
  END x[98]
  PIN x[99]
    DIRECTION INPUT ;
    USE SIGNAL ;
    PORT
      LAYER M4 ;
        RECT  0.054 25.488 0.138 25.512 ;
    END
  END x[99]
  PIN x[9]
    DIRECTION INPUT ;
    USE SIGNAL ;
    PORT
      LAYER M4 ;
        RECT  0.054 7.2 0.138 7.224 ;
    END
  END x[9]
  PIN VDD
    DIRECTION INOUT ;
    USE POWER ;
    PORT
      LAYER M5 ;
        RECT  10.692 2.151 10.812 62.649 ;
        RECT  7.992 2.151 8.112 62.649 ;
        RECT  5.292 2.151 5.412 62.649 ;
        RECT  2.592 2.151 2.712 62.649 ;
    END
  END VDD
  PIN VSS
    DIRECTION INOUT ;
    USE GROUND ;
    PORT
      LAYER M5 ;
        RECT  10.5 2.137 10.62 62.663 ;
        RECT  7.8 2.137 7.92 62.663 ;
        RECT  5.1 2.137 5.22 62.663 ;
        RECT  2.4 2.137 2.52 62.663 ;
    END
  END VSS
  # OT_OBS_CLOSED layer=M5 d_um=1.536 added=78
  OBS
    LAYER RVTN ;
     RECT  2.16 2.16 12.96 2.295 ;
     RECT  2.16 2.565 12.96 2.835 ;
     RECT  2.16 3.105 12.96 3.375 ;
     RECT  2.16 3.645 12.96 3.915 ;
     RECT  2.16 4.185 12.96 4.455 ;
     RECT  2.16 4.725 12.96 4.995 ;
     RECT  2.16 5.265 12.96 5.535 ;
     RECT  2.16 5.805 12.96 6.075 ;
     RECT  2.16 6.345 12.96 6.615 ;
     RECT  2.16 6.885 12.96 7.155 ;
     RECT  2.16 7.425 12.96 7.695 ;
     RECT  2.16 7.965 12.96 8.235 ;
     RECT  2.16 8.505 12.96 8.775 ;
     RECT  2.16 9.045 12.96 9.315 ;
     RECT  2.16 9.585 12.96 9.855 ;
     RECT  2.16 10.125 12.96 10.395 ;
     RECT  2.16 10.665 12.96 10.935 ;
     RECT  2.16 11.205 12.96 11.475 ;
     RECT  2.16 11.745 12.96 12.015 ;
     RECT  2.16 12.285 12.96 12.555 ;
     RECT  2.16 12.825 12.96 13.095 ;
     RECT  2.16 13.365 12.96 13.635 ;
     RECT  2.16 13.905 12.96 14.175 ;
     RECT  2.16 14.445 12.96 14.715 ;
     RECT  2.16 14.985 12.96 15.255 ;
     RECT  2.16 15.525 12.96 15.795 ;
     RECT  2.16 16.065 12.96 16.335 ;
     RECT  2.16 16.605 12.96 16.875 ;
     RECT  2.16 17.145 12.96 17.415 ;
     RECT  2.16 17.685 12.96 17.955 ;
     RECT  2.16 18.225 12.96 18.495 ;
     RECT  2.16 18.765 12.96 19.035 ;
     RECT  2.16 19.305 12.96 19.575 ;
     RECT  2.16 19.845 12.96 20.115 ;
     RECT  2.16 20.385 12.96 20.655 ;
     RECT  2.16 20.925 12.96 21.195 ;
     RECT  2.16 21.465 12.96 21.735 ;
     RECT  2.16 22.005 12.96 22.275 ;
     RECT  2.16 22.545 12.96 22.815 ;
     RECT  2.16 23.085 12.96 23.355 ;
     RECT  2.16 23.625 12.96 23.895 ;
     RECT  2.16 24.165 12.96 24.435 ;
     RECT  2.16 24.705 12.96 24.975 ;
     RECT  2.16 25.245 12.96 25.515 ;
     RECT  2.16 25.785 12.96 26.055 ;
     RECT  2.16 26.325 12.96 26.595 ;
     RECT  2.16 26.865 12.96 27.135 ;
     RECT  2.16 27.405 12.96 27.675 ;
     RECT  2.16 27.945 12.96 28.215 ;
     RECT  2.16 28.485 12.96 28.755 ;
     RECT  2.16 29.025 12.96 29.295 ;
     RECT  2.16 29.565 12.96 29.835 ;
     RECT  2.16 30.105 12.96 30.375 ;
     RECT  2.16 30.645 12.96 30.915 ;
     RECT  2.16 31.185 12.96 31.455 ;
     RECT  2.16 31.725 12.96 31.995 ;
     RECT  2.16 32.265 12.96 32.535 ;
     RECT  2.16 32.805 12.96 33.075 ;
     RECT  2.16 33.345 12.96 33.615 ;
     RECT  2.16 33.885 12.96 34.155 ;
     RECT  2.16 34.425 12.96 34.695 ;
     RECT  2.16 34.965 12.96 35.235 ;
     RECT  2.16 35.505 12.96 35.775 ;
     RECT  2.16 36.045 12.96 36.315 ;
     RECT  2.16 36.585 12.96 36.855 ;
     RECT  2.16 37.125 12.96 37.395 ;
     RECT  2.16 37.665 12.96 37.935 ;
     RECT  2.16 38.205 12.96 38.475 ;
     RECT  2.16 38.745 12.96 39.015 ;
     RECT  2.16 39.285 12.96 39.555 ;
     RECT  2.16 39.825 12.96 40.095 ;
     RECT  2.16 40.365 12.96 40.635 ;
     RECT  2.16 40.905 12.96 41.175 ;
     RECT  2.16 41.445 12.96 41.715 ;
     RECT  2.16 41.985 12.96 42.255 ;
     RECT  2.16 42.525 12.96 42.795 ;
     RECT  2.16 43.065 12.96 43.335 ;
     RECT  2.16 43.605 12.96 43.875 ;
     RECT  2.16 44.145 12.96 44.415 ;
     RECT  2.16 44.685 12.96 44.955 ;
     RECT  2.16 45.225 12.96 45.495 ;
     RECT  2.16 45.765 12.96 46.035 ;
     RECT  2.16 46.305 12.96 46.575 ;
     RECT  2.16 46.845 12.96 47.115 ;
     RECT  2.16 47.385 12.96 47.655 ;
     RECT  2.16 47.925 12.96 48.195 ;
     RECT  2.16 48.465 12.96 48.735 ;
     RECT  2.16 49.005 12.96 49.275 ;
     RECT  2.16 49.545 12.96 49.815 ;
     RECT  2.16 50.085 12.96 50.355 ;
     RECT  2.16 50.625 12.96 50.895 ;
     RECT  2.16 51.165 12.96 51.435 ;
     RECT  2.16 51.705 12.96 51.975 ;
     RECT  2.16 52.245 12.96 52.515 ;
     RECT  2.16 52.785 12.96 53.055 ;
     RECT  2.16 53.325 12.96 53.595 ;
     RECT  2.16 53.865 12.96 54.135 ;
     RECT  2.16 54.405 12.96 54.675 ;
     RECT  2.16 54.945 12.96 55.215 ;
     RECT  2.16 55.485 12.96 55.755 ;
     RECT  2.16 56.025 12.96 56.295 ;
     RECT  2.16 56.565 12.96 56.835 ;
     RECT  2.16 57.105 12.96 57.375 ;
     RECT  2.16 57.645 12.96 57.915 ;
     RECT  2.16 58.185 12.96 58.455 ;
     RECT  2.16 58.725 12.96 58.995 ;
     RECT  2.16 59.265 12.96 59.535 ;
     RECT  2.16 59.805 12.96 60.075 ;
     RECT  2.16 60.345 12.96 60.615 ;
     RECT  2.16 60.885 12.96 61.155 ;
     RECT  2.16 61.425 12.96 61.695 ;
     RECT  2.16 61.965 12.96 62.235 ;
     RECT  2.16 62.505 12.96 62.64 ;
    LAYER RVTP ;
     RECT  2.16 2.295 12.96 2.565 ;
     RECT  2.16 2.835 12.96 3.105 ;
     RECT  2.16 3.375 12.96 3.645 ;
     RECT  2.16 3.915 12.96 4.185 ;
     RECT  2.16 4.455 12.96 4.725 ;
     RECT  2.16 4.995 12.96 5.265 ;
     RECT  2.16 5.535 12.96 5.805 ;
     RECT  2.16 6.075 12.96 6.345 ;
     RECT  2.16 6.615 12.96 6.885 ;
     RECT  2.16 7.155 12.96 7.425 ;
     RECT  2.16 7.695 12.96 7.965 ;
     RECT  2.16 8.235 12.96 8.505 ;
     RECT  2.16 8.775 12.96 9.045 ;
     RECT  2.16 9.315 12.96 9.585 ;
     RECT  2.16 9.855 12.96 10.125 ;
     RECT  2.16 10.395 12.96 10.665 ;
     RECT  2.16 10.935 12.96 11.205 ;
     RECT  2.16 11.475 12.96 11.745 ;
     RECT  2.16 12.015 12.96 12.285 ;
     RECT  2.16 12.555 12.96 12.825 ;
     RECT  2.16 13.095 12.96 13.365 ;
     RECT  2.16 13.635 12.96 13.905 ;
     RECT  2.16 14.175 12.96 14.445 ;
     RECT  2.16 14.715 12.96 14.985 ;
     RECT  2.16 15.255 12.96 15.525 ;
     RECT  2.16 15.795 12.96 16.065 ;
     RECT  2.16 16.335 12.96 16.605 ;
     RECT  2.16 16.875 12.96 17.145 ;
     RECT  2.16 17.415 12.96 17.685 ;
     RECT  2.16 17.955 12.96 18.225 ;
     RECT  2.16 18.495 12.96 18.765 ;
     RECT  2.16 19.035 12.96 19.305 ;
     RECT  2.16 19.575 12.96 19.845 ;
     RECT  2.16 20.115 12.96 20.385 ;
     RECT  2.16 20.655 12.96 20.925 ;
     RECT  2.16 21.195 12.96 21.465 ;
     RECT  2.16 21.735 12.96 22.005 ;
     RECT  2.16 22.275 12.96 22.545 ;
     RECT  2.16 22.815 12.96 23.085 ;
     RECT  2.16 23.355 12.96 23.625 ;
     RECT  2.16 23.895 12.96 24.165 ;
     RECT  2.16 24.435 12.96 24.705 ;
     RECT  2.16 24.975 12.96 25.245 ;
     RECT  2.16 25.515 12.96 25.785 ;
     RECT  2.16 26.055 12.96 26.325 ;
     RECT  2.16 26.595 12.96 26.865 ;
     RECT  2.16 27.135 12.96 27.405 ;
     RECT  2.16 27.675 12.96 27.945 ;
     RECT  2.16 28.215 12.96 28.485 ;
     RECT  2.16 28.755 12.96 29.025 ;
     RECT  2.16 29.295 12.96 29.565 ;
     RECT  2.16 29.835 12.96 30.105 ;
     RECT  2.16 30.375 12.96 30.645 ;
     RECT  2.16 30.915 12.96 31.185 ;
     RECT  2.16 31.455 12.96 31.725 ;
     RECT  2.16 31.995 12.96 32.265 ;
     RECT  2.16 32.535 12.96 32.805 ;
     RECT  2.16 33.075 12.96 33.345 ;
     RECT  2.16 33.615 12.96 33.885 ;
     RECT  2.16 34.155 12.96 34.425 ;
     RECT  2.16 34.695 12.96 34.965 ;
     RECT  2.16 35.235 12.96 35.505 ;
     RECT  2.16 35.775 12.96 36.045 ;
     RECT  2.16 36.315 12.96 36.585 ;
     RECT  2.16 36.855 12.96 37.125 ;
     RECT  2.16 37.395 12.96 37.665 ;
     RECT  2.16 37.935 12.96 38.205 ;
     RECT  2.16 38.475 12.96 38.745 ;
     RECT  2.16 39.015 12.96 39.285 ;
     RECT  2.16 39.555 12.96 39.825 ;
     RECT  2.16 40.095 12.96 40.365 ;
     RECT  2.16 40.635 12.96 40.905 ;
     RECT  2.16 41.175 12.96 41.445 ;
     RECT  2.16 41.715 12.96 41.985 ;
     RECT  2.16 42.255 12.96 42.525 ;
     RECT  2.16 42.795 12.96 43.065 ;
     RECT  2.16 43.335 12.96 43.605 ;
     RECT  2.16 43.875 12.96 44.145 ;
     RECT  2.16 44.415 12.96 44.685 ;
     RECT  2.16 44.955 12.96 45.225 ;
     RECT  2.16 45.495 12.96 45.765 ;
     RECT  2.16 46.035 12.96 46.305 ;
     RECT  2.16 46.575 12.96 46.845 ;
     RECT  2.16 47.115 12.96 47.385 ;
     RECT  2.16 47.655 12.96 47.925 ;
     RECT  2.16 48.195 12.96 48.465 ;
     RECT  2.16 48.735 12.96 49.005 ;
     RECT  2.16 49.275 12.96 49.545 ;
     RECT  2.16 49.815 12.96 50.085 ;
     RECT  2.16 50.355 12.96 50.625 ;
     RECT  2.16 50.895 12.96 51.165 ;
     RECT  2.16 51.435 12.96 51.705 ;
     RECT  2.16 51.975 12.96 52.245 ;
     RECT  2.16 52.515 12.96 52.785 ;
     RECT  2.16 53.055 12.96 53.325 ;
     RECT  2.16 53.595 12.96 53.865 ;
     RECT  2.16 54.135 12.96 54.405 ;
     RECT  2.16 54.675 12.96 54.945 ;
     RECT  2.16 55.215 12.96 55.485 ;
     RECT  2.16 55.755 12.96 56.025 ;
     RECT  2.16 56.295 12.96 56.565 ;
     RECT  2.16 56.835 12.96 57.105 ;
     RECT  2.16 57.375 12.96 57.645 ;
     RECT  2.16 57.915 12.96 58.185 ;
     RECT  2.16 58.455 12.96 58.725 ;
     RECT  2.16 58.995 12.96 59.265 ;
     RECT  2.16 59.535 12.96 59.805 ;
     RECT  2.16 60.075 12.96 60.345 ;
     RECT  2.16 60.615 12.96 60.885 ;
     RECT  2.16 61.155 12.96 61.425 ;
     RECT  2.16 61.695 12.96 61.965 ;
     RECT  2.16 62.235 12.96 62.505 ;
    LAYER M1 ;
     RECT  2.16 2.151 12.96 62.649 ;
    LAYER M2 ;
     RECT  0.535 5.31 2.16 5.328 ;
     RECT  0.139 30.654 2.16 30.672 ;
     RECT  0.535 57.996 2.16 58.014 ;
     RECT  2.16 2.151 12.96 62.649 ;
     RECT  12.96 5.076 13.091 59.724 ;
     RECT  13.091 39.636 13.127 59.724 ;
     RECT  13.091 19.746 13.595 33.336 ;
     RECT  13.091 5.076 13.667 18.954 ;
     RECT  13.595 22.446 13.667 33.336 ;
     RECT  13.091 34.092 13.667 38.664 ;
     RECT  13.127 39.726 13.667 59.724 ;
     RECT  13.667 5.076 13.703 9.774 ;
     RECT  13.667 54.576 14.171 59.724 ;
     RECT  13.667 12.186 14.207 13.554 ;
     RECT  13.595 19.746 14.207 21.654 ;
     RECT  13.667 23.256 14.207 24.354 ;
     RECT  13.667 25.416 14.207 26.514 ;
     RECT  13.667 27.306 14.207 27.864 ;
     RECT  13.667 28.656 14.207 28.944 ;
     RECT  13.667 37.836 14.207 38.664 ;
     RECT  13.667 49.176 14.207 49.464 ;
     RECT  14.171 54.576 14.207 57.294 ;
     RECT  13.703 5.616 14.243 9.774 ;
     RECT  13.667 10.836 14.243 11.394 ;
     RECT  14.207 12.186 14.243 12.474 ;
     RECT  14.207 13.536 14.243 13.554 ;
     RECT  13.667 14.346 14.243 14.634 ;
     RECT  13.667 15.696 14.243 16.254 ;
     RECT  13.667 17.046 14.243 17.136 ;
     RECT  13.667 18.702 14.243 18.72 ;
     RECT  14.207 19.746 14.243 19.872 ;
     RECT  13.667 22.446 14.243 22.464 ;
     RECT  14.207 23.256 14.243 23.274 ;
     RECT  14.207 24.066 14.243 24.084 ;
     RECT  14.207 25.416 14.243 25.434 ;
     RECT  14.207 26.226 14.243 26.244 ;
     RECT  14.207 27.306 14.243 27.594 ;
     RECT  14.207 28.926 14.243 28.944 ;
     RECT  13.667 29.736 14.243 29.754 ;
     RECT  13.667 30.546 14.243 33.336 ;
     RECT  13.667 34.092 14.243 34.11 ;
     RECT  13.667 34.866 14.243 36.774 ;
     RECT  14.207 37.836 14.243 37.854 ;
     RECT  13.667 40.536 14.243 41.904 ;
     RECT  13.667 42.696 14.243 43.596 ;
     RECT  13.667 44.352 14.243 44.37 ;
     RECT  13.667 45.396 14.243 45.756 ;
     RECT  13.667 46.746 14.243 46.764 ;
     RECT  13.667 47.556 14.243 48.384 ;
     RECT  14.207 49.176 14.243 49.194 ;
     RECT  13.667 50.526 14.243 50.544 ;
     RECT  13.667 51.336 14.243 52.434 ;
     RECT  13.667 53.226 14.243 53.244 ;
     RECT  14.207 54.576 14.243 57.024 ;
     RECT  14.171 58.086 14.243 59.724 ;
     RECT  14.243 5.616 14.279 6.84 ;
     RECT  14.243 9.288 14.279 9.306 ;
     RECT  14.243 17.118 14.279 17.136 ;
     RECT  14.207 20.628 14.279 21.654 ;
     RECT  14.243 30.888 14.279 31.554 ;
     RECT  14.243 35.442 14.279 35.802 ;
     RECT  14.243 36.594 14.279 36.612 ;
     RECT  14.207 38.646 14.279 38.664 ;
     RECT  14.243 41.616 14.279 41.706 ;
     RECT  14.243 51.786 14.279 51.804 ;
     RECT  14.279 30.888 14.315 30.906 ;
     RECT  14.279 5.616 14.963 5.634 ;
     RECT  14.279 6.822 14.963 6.84 ;
     RECT  14.243 11.376 14.963 11.394 ;
     RECT  14.243 12.456 14.963 12.474 ;
     RECT  14.243 19.854 14.963 19.872 ;
     RECT  14.279 20.628 14.963 20.646 ;
     RECT  14.279 21.636 14.963 21.654 ;
     RECT  14.279 35.442 14.963 35.46 ;
     RECT  14.279 41.616 14.963 41.634 ;
     RECT  14.243 43.578 14.963 43.596 ;
     RECT  14.243 45.738 14.963 45.756 ;
     RECT  14.243 47.628 14.963 47.646 ;
     RECT  14.243 55.224 14.963 55.242 ;
    LAYER M3 ;
     RECT  2.415 2.143 2.505 2.413 ;
     RECT  5.115 2.143 5.205 2.413 ;
     RECT  7.815 2.143 7.905 2.413 ;
     RECT  10.515 2.143 10.605 2.413 ;
     RECT  9.648 0.523 9.666 2.839 ;
     RECT  9.576 2.839 9.666 2.867 ;
     RECT  12.348 5.035 12.834 5.341 ;
     RECT  13.68 5.071 13.698 5.341 ;
     RECT  2.415 2.413 2.697 5.419 ;
     RECT  9.576 2.867 9.594 5.431 ;
     RECT  12.348 5.341 13.698 5.453 ;
     RECT  12.348 5.453 13.086 5.459 ;
     RECT  3.6 5.341 3.618 5.539 ;
     RECT  5.115 2.413 5.397 5.539 ;
     RECT  6.192 5.431 6.21 5.539 ;
     RECT  10.515 2.413 10.797 5.539 ;
     RECT  2.304 5.419 2.697 5.575 ;
     RECT  3.6 5.539 4.122 5.575 ;
     RECT  5.115 5.539 6.21 5.575 ;
     RECT  9.36 5.431 9.594 5.575 ;
     RECT  10.515 5.539 10.962 5.575 ;
     RECT  2.304 5.575 6.21 5.611 ;
     RECT  7.815 2.413 8.097 5.611 ;
     RECT  7.815 5.611 8.298 5.659 ;
     RECT  9.216 5.575 10.962 5.659 ;
     RECT  14.94 5.611 14.958 5.659 ;
     RECT  14.22 5.659 14.958 5.729 ;
     RECT  0.54 5.305 0.558 5.837 ;
     RECT  2.304 5.611 7.038 5.881 ;
     RECT  7.815 5.659 10.962 5.881 ;
     RECT  14.256 5.729 14.958 5.933 ;
     RECT  2.304 5.881 10.962 6.277 ;
     RECT  2.304 6.277 11.682 6.349 ;
     RECT  12.456 5.459 13.086 6.349 ;
     RECT  2.304 6.349 13.086 6.461 ;
     RECT  14.256 5.933 14.274 6.817 ;
     RECT  14.256 6.817 14.958 6.989 ;
     RECT  2.304 6.461 12.618 7.079 ;
     RECT  2.304 7.079 12.582 7.799 ;
     RECT  2.304 7.799 12.114 8.735 ;
     RECT  13.356 8.545 13.374 8.779 ;
     RECT  2.34 8.735 12.114 8.851 ;
     RECT  13.068 8.779 13.374 8.851 ;
     RECT  2.34 8.851 13.374 8.969 ;
     RECT  3.456 8.969 13.374 9.005 ;
     RECT  3.924 9.005 13.374 9.011 ;
     RECT  14.22 7.243 14.238 9.067 ;
     RECT  3.96 9.011 13.374 9.113 ;
     RECT  4.32 9.113 13.374 9.239 ;
     RECT  14.22 9.067 14.274 9.311 ;
     RECT  4.32 9.239 11.826 9.437 ;
     RECT  12.636 9.239 13.374 9.509 ;
     RECT  2.34 8.969 2.697 9.643 ;
     RECT  14.22 9.311 14.238 9.779 ;
     RECT  2.304 9.643 2.697 9.823 ;
     RECT  2.304 9.823 2.826 9.859 ;
     RECT  3.564 9.823 3.582 9.859 ;
     RECT  13.356 9.509 13.374 9.883 ;
     RECT  7.815 9.437 11.826 10.057 ;
     RECT  2.304 9.859 3.582 10.165 ;
     RECT  4.32 9.437 7.002 10.165 ;
     RECT  2.304 10.165 7.002 10.357 ;
     RECT  7.815 10.057 12.15 10.357 ;
     RECT  13.356 9.883 13.662 10.651 ;
     RECT  2.304 10.357 12.15 10.741 ;
     RECT  2.304 10.741 12.51 10.859 ;
     RECT  13.356 10.651 14.238 11.213 ;
     RECT  2.304 10.859 12.438 11.399 ;
     RECT  14.94 11.371 14.958 11.453 ;
     RECT  13.356 11.213 13.662 11.741 ;
     RECT  14.184 11.947 14.238 12.209 ;
     RECT  2.304 11.399 12.294 12.217 ;
     RECT  2.304 12.217 12.474 12.451 ;
     RECT  13.356 11.741 13.374 12.451 ;
     RECT  2.304 12.451 13.374 12.475 ;
     RECT  14.184 12.209 14.202 12.475 ;
     RECT  14.94 12.451 14.958 12.797 ;
     RECT  2.304 12.475 14.202 13.531 ;
     RECT  2.304 13.531 14.238 13.568 ;
     RECT  2.304 13.568 13.662 13.595 ;
     RECT  9.612 13.595 13.662 14.093 ;
     RECT  9.612 14.093 13.374 14.171 ;
     RECT  2.304 13.595 8.874 14.377 ;
     RECT  9.612 14.171 12.51 14.377 ;
     RECT  13.356 14.171 13.374 14.872 ;
     RECT  14.22 14.341 14.238 14.872 ;
     RECT  2.304 14.377 12.51 14.945 ;
     RECT  6.696 14.945 12.51 15.025 ;
     RECT  6.696 15.025 12.618 15.179 ;
     RECT  2.304 14.945 5.886 15.215 ;
     RECT  7.056 15.179 12.618 15.521 ;
     RECT  12.492 15.521 12.618 15.835 ;
     RECT  13.356 14.872 14.238 15.835 ;
     RECT  7.056 15.521 7.074 15.869 ;
     RECT  2.304 15.215 5.85 16.025 ;
     RECT  7.815 15.521 11.754 16.375 ;
     RECT  12.492 15.835 14.238 16.375 ;
     RECT  6.84 15.997 6.858 16.609 ;
     RECT  6.804 16.609 6.858 16.681 ;
     RECT  6.732 16.681 6.858 16.799 ;
     RECT  7.815 16.375 14.238 16.915 ;
     RECT  6.624 16.891 6.642 16.943 ;
     RECT  2.304 16.025 5.814 16.951 ;
     RECT  2.304 16.951 5.85 17.105 ;
     RECT  7.416 16.915 14.238 17.113 ;
     RECT  7.416 17.113 14.274 17.411 ;
     RECT  9.18 17.411 14.274 17.549 ;
     RECT  7.416 17.411 8.334 17.581 ;
     RECT  9.18 17.549 13.662 17.879 ;
     RECT  2.304 17.105 5.562 17.959 ;
     RECT  2.304 17.959 5.598 18.031 ;
     RECT  7.164 17.581 8.334 18.157 ;
     RECT  2.304 18.031 5.922 18.229 ;
     RECT  7.164 18.157 8.406 18.229 ;
     RECT  7.092 18.229 8.406 18.235 ;
     RECT  9.18 17.879 12.294 18.235 ;
     RECT  2.304 18.229 6.318 18.301 ;
     RECT  7.092 18.235 12.294 18.301 ;
     RECT  13.356 17.879 13.662 18.571 ;
     RECT  2.304 18.301 12.294 18.661 ;
     RECT  13.356 18.571 14.238 18.661 ;
     RECT  2.304 18.661 14.238 18.959 ;
     RECT  2.304 18.959 13.374 19.229 ;
     RECT  13.068 19.229 13.374 19.301 ;
     RECT  14.184 18.959 14.238 19.849 ;
     RECT  2.304 19.229 12.042 20.011 ;
     RECT  2.304 20.011 12.51 20.111 ;
     RECT  14.184 19.849 14.958 20.651 ;
     RECT  13.356 19.301 13.374 20.683 ;
     RECT  14.184 20.651 14.274 20.683 ;
     RECT  2.304 20.111 12.474 21.091 ;
     RECT  13.356 20.683 14.274 21.091 ;
     RECT  2.304 21.091 14.274 21.119 ;
     RECT  14.94 21.631 14.958 21.725 ;
     RECT  12.384 21.119 13.95 22.073 ;
     RECT  2.304 21.119 11.646 22.171 ;
     RECT  12.384 22.073 12.618 22.171 ;
     RECT  2.304 22.171 12.618 22.199 ;
     RECT  13.356 22.073 13.95 22.441 ;
     RECT  2.304 22.199 12.474 22.469 ;
     RECT  7.2 22.469 12.474 22.505 ;
     RECT  2.304 22.469 6.462 22.621 ;
     RECT  2.268 22.621 6.462 22.685 ;
     RECT  7.2 22.505 12.222 22.811 ;
     RECT  7.815 22.811 12.222 23.395 ;
     RECT  13.356 22.441 14.238 23.395 ;
     RECT  7.815 23.395 14.238 23.549 ;
     RECT  2.304 22.685 6.462 23.557 ;
     RECT  2.304 23.557 6.858 23.729 ;
     RECT  7.815 23.549 12.366 23.851 ;
     RECT  7.2 23.851 12.366 24.475 ;
     RECT  13.356 23.549 14.238 24.475 ;
     RECT  2.304 23.729 6.462 24.673 ;
     RECT  7.2 24.475 14.238 24.673 ;
     RECT  2.304 24.673 14.238 24.899 ;
     RECT  2.304 24.899 12.366 26.095 ;
     RECT  13.356 24.899 14.238 26.249 ;
     RECT  2.304 26.095 12.474 26.905 ;
     RECT  13.356 26.249 14.202 26.905 ;
     RECT  2.304 26.905 14.202 26.971 ;
     RECT  2.304 26.971 14.238 28.139 ;
     RECT  2.304 28.139 12.618 30.029 ;
     RECT  2.304 30.029 12.366 30.335 ;
     RECT  13.356 28.139 14.238 30.427 ;
     RECT  2.304 30.335 9.738 30.605 ;
     RECT  0.144 30.331 0.162 30.797 ;
     RECT  13.356 30.427 14.274 30.883 ;
     RECT  10.515 30.335 12.366 30.955 ;
     RECT  10.515 30.955 12.474 30.991 ;
     RECT  13.356 30.883 14.31 30.991 ;
     RECT  10.515 30.991 14.31 31.181 ;
     RECT  13.356 31.181 14.31 31.229 ;
     RECT  2.415 30.605 9.738 31.261 ;
     RECT  10.515 31.181 12.474 31.261 ;
     RECT  13.356 31.229 14.274 31.559 ;
     RECT  2.415 31.261 12.474 31.579 ;
     RECT  2.376 31.579 12.474 31.765 ;
     RECT  2.304 31.765 12.474 32.071 ;
     RECT  13.356 31.559 14.238 32.071 ;
     RECT  2.304 32.071 14.238 32.369 ;
     RECT  2.304 32.369 12.582 32.459 ;
     RECT  2.304 32.459 12.546 32.971 ;
     RECT  2.232 32.971 12.546 33.035 ;
     RECT  2.304 33.035 12.546 33.305 ;
     RECT  13.356 32.369 14.238 33.341 ;
     RECT  7.74 33.305 12.546 33.385 ;
     RECT  13.356 33.341 13.95 33.385 ;
     RECT  7.74 33.385 13.95 34.075 ;
     RECT  7.74 34.075 14.238 34.115 ;
     RECT  2.304 33.305 7.002 34.315 ;
     RECT  7.74 34.115 13.95 34.315 ;
     RECT  2.304 34.315 13.95 34.385 ;
     RECT  7.74 34.385 13.95 34.691 ;
     RECT  13.356 34.691 13.95 34.861 ;
     RECT  13.356 34.861 14.238 34.925 ;
     RECT  14.94 35.419 14.958 35.465 ;
     RECT  2.304 34.385 7.002 35.509 ;
     RECT  7.74 34.691 12.51 35.509 ;
     RECT  2.304 35.509 12.51 35.545 ;
     RECT  2.304 35.545 12.546 35.549 ;
     RECT  7.74 35.549 12.546 35.581 ;
     RECT  13.356 34.925 13.95 35.581 ;
     RECT  7.74 35.581 13.95 35.659 ;
     RECT  2.304 35.549 7.002 35.699 ;
     RECT  2.304 35.699 6.534 36.472 ;
     RECT  2.304 36.472 6.894 36.553 ;
     RECT  7.74 35.659 14.274 36.553 ;
     RECT  2.304 36.553 14.274 36.617 ;
     RECT  2.304 36.617 14.238 37.243 ;
     RECT  2.268 37.243 14.238 37.355 ;
     RECT  2.304 37.355 14.238 37.859 ;
     RECT  2.304 37.859 14.202 38.641 ;
     RECT  2.304 38.641 14.274 38.861 ;
     RECT  2.304 38.861 13.95 39.883 ;
     RECT  2.268 39.883 13.95 40.055 ;
     RECT  2.304 40.055 13.95 40.411 ;
     RECT  2.304 40.411 14.238 41.369 ;
     RECT  13.356 41.369 14.238 41.467 ;
     RECT  13.356 41.467 14.274 41.611 ;
     RECT  13.356 41.611 14.958 41.789 ;
     RECT  2.304 41.369 12.582 42.331 ;
     RECT  13.356 41.789 14.238 42.331 ;
     RECT  2.304 42.331 14.238 42.899 ;
     RECT  2.304 42.899 12.618 42.989 ;
     RECT  2.304 42.989 12.474 43.132 ;
     RECT  2.268 43.132 12.474 43.295 ;
     RECT  2.304 43.295 12.474 43.331 ;
     RECT  13.356 42.899 14.238 43.529 ;
     RECT  14.94 43.573 14.958 43.613 ;
     RECT  7.38 43.331 12.474 43.799 ;
     RECT  2.304 43.331 6.606 43.805 ;
     RECT  2.34 43.805 6.606 43.835 ;
     RECT  13.356 43.529 13.95 44.347 ;
     RECT  13.356 44.347 14.238 44.384 ;
     RECT  2.412 43.835 6.606 44.419 ;
     RECT  7.38 43.799 12.33 44.419 ;
     RECT  2.412 44.419 12.33 44.587 ;
     RECT  2.304 44.587 12.33 44.851 ;
     RECT  13.356 44.384 13.95 44.851 ;
     RECT  2.304 44.851 13.95 45.163 ;
     RECT  2.304 45.163 14.238 45.355 ;
     RECT  2.268 45.355 14.238 45.403 ;
     RECT  2.268 45.403 14.958 45.455 ;
     RECT  2.304 45.455 14.958 46.229 ;
     RECT  2.304 46.229 12.618 46.841 ;
     RECT  2.304 46.841 12.546 47.219 ;
     RECT  7.236 47.219 12.546 47.261 ;
     RECT  2.304 47.219 6.21 47.309 ;
     RECT  13.356 46.229 14.958 47.651 ;
     RECT  7.38 47.261 12.546 47.695 ;
     RECT  2.304 47.309 5.85 47.849 ;
     RECT  7.38 47.695 12.618 47.849 ;
     RECT  7.38 47.849 12.51 48.361 ;
     RECT  6.732 48.361 12.51 48.433 ;
     RECT  6.552 48.433 12.51 48.811 ;
     RECT  13.356 47.651 14.238 48.811 ;
     RECT  6.552 48.811 14.238 48.929 ;
     RECT  13.356 48.929 14.238 49.199 ;
     RECT  2.304 47.849 5.634 49.855 ;
     RECT  6.552 48.929 12.618 49.855 ;
     RECT  2.304 49.855 12.618 49.891 ;
     RECT  13.356 49.199 14.202 49.891 ;
     RECT  2.304 49.891 14.202 50.155 ;
     RECT  2.304 50.155 14.238 50.459 ;
     RECT  3.636 50.459 14.238 51.211 ;
     RECT  3.636 51.211 14.274 51.269 ;
     RECT  2.304 50.459 2.697 51.307 ;
     RECT  3.636 51.269 12.582 51.307 ;
     RECT  2.304 51.307 12.582 51.485 ;
     RECT  3.528 51.485 12.582 51.629 ;
     RECT  13.356 51.269 14.274 51.809 ;
     RECT  3.744 51.629 12.582 52.007 ;
     RECT  6.84 52.007 12.582 52.051 ;
     RECT  13.356 51.809 14.238 52.051 ;
     RECT  3.744 52.007 5.958 52.439 ;
     RECT  2.304 51.485 2.79 52.789 ;
     RECT  3.744 52.439 4.122 52.789 ;
     RECT  2.304 52.789 4.122 53.015 ;
     RECT  3.78 53.015 4.122 53.365 ;
     RECT  5.004 52.439 5.958 53.365 ;
     RECT  3.78 53.365 5.958 53.941 ;
     RECT  6.84 52.051 14.238 53.941 ;
     RECT  3.78 53.941 14.238 54.091 ;
     RECT  3.528 54.091 14.238 54.139 ;
     RECT  3.42 54.139 14.238 54.329 ;
     RECT  3.528 54.329 14.238 54.599 ;
     RECT  3.528 54.599 14.202 54.635 ;
     RECT  3.528 54.635 12.474 55.049 ;
     RECT  2.304 53.015 2.697 55.243 ;
     RECT  3.528 55.049 4.014 55.243 ;
     RECT  14.94 54.619 14.958 55.247 ;
     RECT  13.356 54.635 14.202 55.381 ;
     RECT  5.115 55.049 12.474 55.679 ;
     RECT  5.115 55.679 12.402 55.751 ;
     RECT  5.115 55.751 9.738 55.787 ;
     RECT  2.304 55.243 4.014 55.795 ;
     RECT  5.115 55.787 9.198 55.795 ;
     RECT  2.304 55.795 9.198 55.949 ;
     RECT  6.624 55.949 9.198 56.219 ;
     RECT  6.624 56.219 6.642 56.381 ;
     RECT  2.304 55.949 5.814 56.489 ;
     RECT  7.38 56.219 9.198 56.489 ;
     RECT  2.304 56.489 4.23 56.525 ;
     RECT  5.076 56.489 5.814 56.669 ;
     RECT  2.304 56.525 2.697 56.731 ;
     RECT  3.78 56.525 4.23 56.759 ;
     RECT  2.268 56.731 2.697 56.867 ;
     RECT  10.515 55.751 12.402 56.911 ;
     RECT  3.96 56.759 4.23 57.415 ;
     RECT  5.076 56.669 5.397 57.415 ;
     RECT  2.304 56.867 2.697 57.451 ;
     RECT  10.515 56.911 12.474 57.569 ;
     RECT  2.304 57.451 2.862 57.577 ;
     RECT  3.96 57.415 5.397 57.577 ;
     RECT  13.356 55.381 14.238 57.581 ;
     RECT  2.304 57.577 5.67 57.613 ;
     RECT  2.304 57.613 5.742 57.649 ;
     RECT  6.588 57.451 6.606 57.649 ;
     RECT  10.515 57.569 10.797 57.685 ;
     RECT  13.932 57.581 14.238 57.691 ;
     RECT  7.74 56.489 9.198 57.725 ;
     RECT  11.592 57.569 12.474 57.911 ;
     RECT  7.74 57.725 8.982 57.919 ;
     RECT  2.304 57.649 6.606 57.955 ;
     RECT  7.416 57.919 8.982 57.955 ;
     RECT  12.024 57.911 12.474 57.991 ;
     RECT  10.26 57.685 10.797 58.109 ;
     RECT  13.932 57.691 14.958 58.109 ;
     RECT  2.304 57.955 8.982 58.145 ;
     RECT  12.024 57.991 12.654 58.145 ;
     RECT  7.272 58.145 8.982 58.253 ;
     RECT  14.22 58.109 14.958 58.349 ;
     RECT  2.304 58.145 6.462 58.363 ;
     RECT  0.54 57.991 0.558 58.589 ;
     RECT  12.024 58.145 12.222 58.649 ;
     RECT  2.268 58.363 6.462 58.685 ;
     RECT  7.272 58.253 8.91 58.955 ;
     RECT  7.308 58.955 8.91 59.035 ;
     RECT  7.308 59.035 8.946 59.071 ;
     RECT  7.308 59.071 9.378 59.189 ;
     RECT  9.36 59.189 9.378 59.225 ;
     RECT  10.515 58.109 10.797 59.341 ;
     RECT  11.592 59.035 12.006 59.341 ;
     RECT  2.304 58.685 6.462 59.495 ;
     RECT  2.304 59.495 3.762 59.567 ;
     RECT  4.572 59.495 6.462 59.603 ;
     RECT  10.515 59.341 12.006 59.611 ;
     RECT  2.415 59.567 3.762 59.729 ;
     RECT  10.515 59.611 12.582 59.729 ;
     RECT  14.22 58.349 14.238 59.729 ;
     RECT  2.415 59.729 3.222 59.765 ;
     RECT  6.228 59.603 6.462 59.765 ;
     RECT  7.308 59.189 8.097 59.765 ;
     RECT  12.564 59.729 12.582 59.765 ;
     RECT  7.416 59.765 8.097 59.801 ;
     RECT  6.228 59.765 6.246 59.999 ;
     RECT  4.572 59.603 5.397 60.035 ;
     RECT  2.415 59.765 2.697 62.387 ;
     RECT  5.115 60.035 5.397 62.387 ;
     RECT  7.815 59.801 8.097 62.387 ;
     RECT  10.515 59.729 10.797 62.387 ;
     RECT  2.415 62.387 2.505 62.657 ;
     RECT  5.115 62.387 5.205 62.657 ;
     RECT  7.815 62.387 7.905 62.657 ;
     RECT  10.515 62.387 10.605 62.657 ;
    LAYER M4 ;
     RECT  0.085 1.392 0.108 1.416 ;
     RECT  0.085 30.24 0.108 30.264 ;
     RECT  0.108 5.424 2.408 59.4 ;
     RECT  2.408 2.148 2.512 62.652 ;
     RECT  2.512 2.418 2.704 62.382 ;
     RECT  2.704 9.84 2.765 11.496 ;
     RECT  2.704 13.104 2.765 16.584 ;
     RECT  2.704 17.952 2.765 21.24 ;
     RECT  2.704 29.328 2.765 33.624 ;
     RECT  2.765 13.92 2.801 16.584 ;
     RECT  2.704 23.04 2.801 23.064 ;
     RECT  2.704 25.056 2.801 27.144 ;
     RECT  2.765 29.616 2.801 33.624 ;
     RECT  2.704 34.8 2.801 36.888 ;
     RECT  2.704 48.432 2.801 50.136 ;
     RECT  2.704 51.312 2.801 52.296 ;
     RECT  2.704 6.24 2.837 8.232 ;
     RECT  2.765 9.84 2.837 10.68 ;
     RECT  2.765 18.192 2.837 20.616 ;
     RECT  2.801 51.312 2.837 51.48 ;
     RECT  2.704 41.04 2.909 43.368 ;
     RECT  2.801 14.112 3.017 16.392 ;
     RECT  2.801 34.8 3.197 36.264 ;
     RECT  2.801 48.432 3.197 48.456 ;
     RECT  2.837 10.656 3.233 10.68 ;
     RECT  2.704 45.984 3.233 46.008 ;
     RECT  2.704 58.416 3.233 59.208 ;
     RECT  2.909 41.04 3.305 41.976 ;
     RECT  2.801 25.056 3.347 27.096 ;
     RECT  2.837 6.24 3.443 7.896 ;
     RECT  2.909 43.344 3.443 43.368 ;
     RECT  2.837 20.4 3.733 20.616 ;
     RECT  3.197 34.8 3.779 35.352 ;
     RECT  2.801 29.616 3.781 31.368 ;
     RECT  2.801 32.736 3.781 33.624 ;
     RECT  3.781 29.616 3.797 33.624 ;
     RECT  3.779 35.232 3.827 35.352 ;
     RECT  3.733 38.208 3.841 38.232 ;
     RECT  3.797 29.616 3.877 33.672 ;
     RECT  2.704 39.36 3.877 39.384 ;
     RECT  2.837 51.312 3.877 51.336 ;
     RECT  2.704 54.096 3.877 55.272 ;
     RECT  3.877 29.088 3.881 33.672 ;
     RECT  3.877 53.904 3.913 55.272 ;
     RECT  3.347 25.728 3.925 27.096 ;
     RECT  3.877 39.264 3.925 39.384 ;
     RECT  2.801 50.112 3.925 50.136 ;
     RECT  3.877 51.12 3.925 51.912 ;
     RECT  3.913 53.904 3.925 55.32 ;
     RECT  3.925 50.112 3.961 51.912 ;
     RECT  3.877 22.224 3.971 22.248 ;
     RECT  3.841 37.632 3.971 38.232 ;
     RECT  3.961 50.112 3.971 51.336 ;
     RECT  3.881 29.088 3.989 32.76 ;
     RECT  3.305 41.04 3.997 41.736 ;
     RECT  3.913 46.752 3.997 46.776 ;
     RECT  3.925 39.264 4.021 39.528 ;
     RECT  3.017 14.112 4.124 15 ;
     RECT  3.884 8.976 4.237 9 ;
     RECT  2.837 18.672 4.237 19.368 ;
     RECT  3.733 20.4 4.237 21.096 ;
     RECT  4.237 18.672 4.273 21.096 ;
     RECT  4.021 38.688 4.273 39.528 ;
     RECT  3.997 41.04 4.273 41.448 ;
     RECT  3.925 25.728 4.345 27.672 ;
     RECT  4.309 37.584 4.501 37.608 ;
     RECT  4.237 8.544 4.556 9 ;
     RECT  3.989 29.088 4.561 30.984 ;
     RECT  4.345 25.68 4.705 27.672 ;
     RECT  3.233 58.416 4.813 58.68 ;
     RECT  4.813 58.128 4.844 59.304 ;
     RECT  4.556 8.16 4.885 9 ;
     RECT  3.925 53.28 4.885 55.32 ;
     RECT  2.704 56.352 4.885 56.376 ;
     RECT  4.705 25.68 4.933 27.96 ;
     RECT  4.501 36.816 4.949 37.608 ;
     RECT  4.273 38.688 4.949 41.448 ;
     RECT  4.124 14.112 4.981 15.672 ;
     RECT  3.989 32.016 4.981 32.76 ;
     RECT  3.827 35.232 4.981 35.304 ;
     RECT  3.925 44.976 4.981 45 ;
     RECT  4.405 46.08 4.981 46.104 ;
     RECT  4.309 47.616 4.981 47.64 ;
     RECT  3.971 50.112 4.981 51.144 ;
     RECT  4.981 10.368 4.993 10.392 ;
     RECT  4.981 49.776 4.993 51.144 ;
     RECT  3.925 5.472 5.108 5.496 ;
     RECT  3.443 7.152 5.108 7.176 ;
     RECT  4.885 8.16 5.108 9.288 ;
     RECT  4.993 10.32 5.108 10.392 ;
     RECT  4.981 11.664 5.108 11.688 ;
     RECT  3.949 13.056 5.108 13.08 ;
     RECT  4.981 14.112 5.108 16.008 ;
     RECT  4.273 18.672 5.108 21.72 ;
     RECT  4.933 25.008 5.108 27.96 ;
     RECT  4.561 29.04 5.108 30.984 ;
     RECT  4.981 32.016 5.108 32.856 ;
     RECT  4.981 33.936 5.108 35.304 ;
     RECT  4.949 36.816 5.108 41.448 ;
     RECT  4.981 42.432 5.108 42.456 ;
     RECT  4.981 43.536 5.108 43.56 ;
     RECT  4.981 44.976 5.108 46.248 ;
     RECT  4.981 47.616 5.108 48.792 ;
     RECT  4.993 49.776 5.108 51.768 ;
     RECT  4.885 53.28 5.108 56.376 ;
     RECT  4.844 57.504 5.108 59.304 ;
     RECT  5.108 2.148 5.212 62.652 ;
     RECT  5.212 2.418 5.404 62.382 ;
     RECT  5.404 34.8 5.537 35.304 ;
     RECT  5.404 49.488 5.653 50.856 ;
     RECT  5.404 5.472 5.681 9 ;
     RECT  5.404 46.08 5.681 46.248 ;
     RECT  5.653 50.544 5.681 50.856 ;
     RECT  5.404 52.416 5.681 56.376 ;
     RECT  5.404 24.096 5.699 32.856 ;
     RECT  5.537 34.8 5.725 35.16 ;
     RECT  5.699 25.008 5.747 32.856 ;
     RECT  5.747 28.992 5.788 32.856 ;
     RECT  5.747 25.008 5.825 27.96 ;
     RECT  5.681 5.472 6.221 8.184 ;
     RECT  5.404 18.768 6.433 22.248 ;
     RECT  5.404 58.128 6.473 58.152 ;
     RECT  5.404 36.816 6.572 37.608 ;
     RECT  5.404 38.688 6.572 39.528 ;
     RECT  5.404 41.424 6.572 41.448 ;
     RECT  5.404 44.976 6.572 45 ;
     RECT  5.681 46.08 6.572 46.104 ;
     RECT  5.404 12.96 6.613 14.952 ;
     RECT  6.572 41.232 6.613 42.36 ;
     RECT  6.572 44.016 6.613 46.104 ;
     RECT  6.433 18.432 6.62 22.248 ;
     RECT  5.681 56.352 6.653 56.376 ;
     RECT  6.572 16.896 6.659 16.92 ;
     RECT  6.572 36.816 6.659 40.2 ;
     RECT  6.613 41.232 6.659 46.104 ;
     RECT  6.659 45.6 6.689 46.104 ;
     RECT  6.613 12.528 6.7 14.952 ;
     RECT  5.725 35.136 6.709 35.16 ;
     RECT  5.825 25.056 6.721 27.96 ;
     RECT  6.659 43.104 6.733 44.472 ;
     RECT  6.659 36.816 6.757 37.08 ;
     RECT  6.659 38.208 6.761 40.2 ;
     RECT  5.653 49.488 6.761 49.512 ;
     RECT  5.681 52.416 6.764 55.272 ;
     RECT  5.404 10.32 6.785 10.344 ;
     RECT  6.785 10.32 6.829 10.872 ;
     RECT  6.709 35.136 6.829 35.208 ;
     RECT  5.788 29.808 6.853 32.856 ;
     RECT  6.761 38.688 6.853 40.2 ;
     RECT  6.659 41.232 6.853 42.072 ;
     RECT  6.7 12.576 7.045 14.952 ;
     RECT  6.721 25.056 7.117 28.488 ;
     RECT  7.117 24.72 7.148 28.488 ;
     RECT  6.853 29.808 7.148 33.048 ;
     RECT  6.805 34.08 7.148 34.104 ;
     RECT  6.829 35.136 7.148 35.304 ;
     RECT  5.681 50.64 7.148 50.856 ;
     RECT  7.148 29.808 7.151 35.304 ;
     RECT  6.757 36.336 7.151 37.08 ;
     RECT  6.62 18.432 7.189 22.44 ;
     RECT  7.151 29.808 7.189 37.08 ;
     RECT  7.148 50.64 7.189 51.384 ;
     RECT  6.829 10.32 7.196 10.968 ;
     RECT  7.189 18.432 7.225 22.776 ;
     RECT  7.196 47.232 7.237 47.256 ;
     RECT  5.404 48.384 7.237 48.504 ;
     RECT  7.225 17.088 7.333 22.776 ;
     RECT  7.148 23.856 7.333 28.488 ;
     RECT  7.237 47.232 7.381 48.504 ;
     RECT  7.189 50.16 7.381 51.384 ;
     RECT  6.764 52.416 7.381 55.896 ;
     RECT  6.221 5.472 7.808 7.944 ;
     RECT  7.196 9.408 7.808 10.968 ;
     RECT  7.045 12.576 7.808 15.864 ;
     RECT  7.333 17.088 7.808 28.488 ;
     RECT  7.189 29.664 7.808 37.08 ;
     RECT  6.853 38.688 7.808 42.072 ;
     RECT  6.733 43.104 7.808 43.896 ;
     RECT  6.689 45.6 7.808 45.672 ;
     RECT  7.381 47.232 7.808 48.984 ;
     RECT  7.381 50.16 7.808 55.896 ;
     RECT  7.808 2.148 7.912 62.652 ;
     RECT  7.912 2.418 8.104 62.382 ;
     RECT  8.104 9.984 8.243 11.976 ;
     RECT  8.104 13.104 8.243 14.952 ;
     RECT  8.104 57.6 8.243 58.248 ;
     RECT  8.243 9.984 8.339 11.112 ;
     RECT  8.104 19.296 8.345 23.304 ;
     RECT  8.104 40.56 8.531 41.976 ;
     RECT  8.104 30.096 8.533 30.744 ;
     RECT  8.104 50.112 8.597 53.016 ;
     RECT  8.345 21.888 8.675 23.304 ;
     RECT  8.243 13.104 8.741 14.808 ;
     RECT  8.345 19.296 8.741 20.52 ;
     RECT  8.104 5.472 8.813 7.8 ;
     RECT  8.675 21.984 8.813 23.304 ;
     RECT  8.104 17.088 8.849 18.264 ;
     RECT  8.104 48.48 8.849 49.032 ;
     RECT  8.104 24.48 8.857 29.112 ;
     RECT  8.104 32.832 8.867 33.048 ;
     RECT  8.104 34.08 8.867 36.36 ;
     RECT  8.104 38.688 8.867 39.528 ;
     RECT  8.531 40.704 8.867 41.976 ;
     RECT  8.867 34.08 8.885 35.304 ;
     RECT  8.104 46.752 8.885 46.776 ;
     RECT  8.857 24.48 8.893 28.536 ;
     RECT  8.104 44.88 8.908 45.672 ;
     RECT  8.741 13.104 8.913 13.128 ;
     RECT  8.813 6.72 8.915 7.8 ;
     RECT  8.104 8.928 8.915 8.952 ;
     RECT  8.339 9.984 8.915 10.968 ;
     RECT  8.849 48.96 8.915 49.032 ;
     RECT  8.597 50.112 8.915 50.76 ;
     RECT  8.867 41.952 8.957 41.976 ;
     RECT  8.885 34.08 9.029 34.104 ;
     RECT  8.885 35.184 9.029 35.304 ;
     RECT  8.867 36.288 9.029 36.36 ;
     RECT  8.104 43.824 9.029 43.896 ;
     RECT  8.104 54.384 9.029 55.272 ;
     RECT  8.915 7.392 9.173 7.8 ;
     RECT  8.893 24.48 9.203 27.768 ;
     RECT  8.813 5.472 9.245 5.688 ;
     RECT  9.203 24.48 9.281 26.664 ;
     RECT  9.245 5.472 9.389 5.496 ;
     RECT  8.741 19.296 9.425 20.136 ;
     RECT  9.281 25.056 9.533 26.664 ;
     RECT  9.637 0.528 9.731 0.552 ;
     RECT  8.813 21.984 9.817 22.056 ;
     RECT  8.813 23.28 9.817 23.304 ;
     RECT  9.817 21.984 9.877 23.304 ;
     RECT  8.533 30.096 10.213 30.12 ;
     RECT  9.029 36.288 10.249 36.312 ;
     RECT  8.867 38.688 10.249 39.336 ;
     RECT  8.867 32.832 10.261 32.856 ;
     RECT  8.867 40.704 10.261 40.728 ;
     RECT  9.457 42.576 10.261 42.6 ;
     RECT  9.029 43.824 10.261 43.848 ;
     RECT  8.908 44.88 10.261 44.904 ;
     RECT  9.029 35.28 10.268 35.304 ;
     RECT  9.173 7.776 10.309 7.8 ;
     RECT  8.915 10.896 10.309 10.968 ;
     RECT  10.261 31.92 10.309 32.856 ;
     RECT  10.249 36.288 10.309 36.36 ;
     RECT  10.309 12.72 10.349 12.744 ;
     RECT  8.741 14.208 10.357 14.808 ;
     RECT  8.849 17.856 10.357 18.264 ;
     RECT  8.915 48.96 10.357 48.984 ;
     RECT  8.597 52.176 10.357 53.016 ;
     RECT  9.529 15.984 10.465 16.008 ;
     RECT  10.309 6.816 10.508 7.8 ;
     RECT  10.309 8.784 10.508 8.808 ;
     RECT  10.309 9.888 10.508 9.912 ;
     RECT  10.309 10.896 10.508 11.688 ;
     RECT  10.349 12.72 10.508 13.032 ;
     RECT  10.357 14.208 10.508 14.904 ;
     RECT  10.465 15.984 10.508 16.056 ;
     RECT  10.357 17.04 10.508 18.264 ;
     RECT  9.425 19.296 10.508 19.992 ;
     RECT  9.877 21.504 10.508 23.4 ;
     RECT  9.533 25.056 10.508 25.608 ;
     RECT  9.533 26.592 10.508 26.664 ;
     RECT  9.203 27.696 10.508 27.768 ;
     RECT  10.213 29.664 10.508 30.168 ;
     RECT  10.309 31.92 10.508 33.864 ;
     RECT  10.268 35.232 10.508 35.304 ;
     RECT  10.309 36.288 10.508 37.08 ;
     RECT  10.249 38.496 10.508 39.336 ;
     RECT  10.261 40.32 10.508 41.448 ;
     RECT  10.261 42.576 10.508 43.848 ;
     RECT  10.261 44.88 10.508 45.528 ;
     RECT  10.261 46.608 10.508 46.632 ;
     RECT  10.357 47.664 10.508 47.688 ;
     RECT  10.357 48.912 10.508 48.984 ;
     RECT  10.316 50.496 10.508 50.52 ;
     RECT  10.357 52.176 10.508 53.832 ;
     RECT  9.781 55.296 10.508 55.32 ;
     RECT  8.243 57.696 10.508 58.248 ;
     RECT  10.508 2.148 10.612 62.652 ;
     RECT  10.612 2.418 10.804 62.382 ;
     RECT  10.804 16.032 10.973 16.056 ;
     RECT  10.804 38.64 11.333 38.664 ;
     RECT  10.804 54.048 11.729 54.072 ;
     RECT  10.804 8.544 12.125 8.568 ;
     RECT  10.804 41.616 12.449 41.64 ;
     RECT  12.805 6.192 13.057 6.216 ;
     RECT  13.057 33.552 13.093 34.392 ;
     RECT  13.057 38.304 13.093 39.144 ;
     RECT  10.804 57.696 13.345 58.248 ;
     RECT  13.057 13.824 13.489 13.848 ;
     RECT  13.489 13.296 13.525 13.848 ;
     RECT  13.057 15.936 13.525 15.96 ;
     RECT  13.057 21.984 13.561 22.008 ;
     RECT  12.553 28.848 13.561 28.872 ;
     RECT  13.093 38.304 13.561 39.672 ;
     RECT  12.553 49.632 13.597 49.656 ;
     RECT  13.561 54.096 13.597 54.12 ;
     RECT  13.561 10.896 13.633 10.92 ;
     RECT  13.525 13.008 13.633 13.848 ;
     RECT  13.525 15.936 13.633 16.2 ;
     RECT  13.057 19.104 13.633 19.128 ;
     RECT  13.561 21.456 13.633 22.248 ;
     RECT  13.597 25.152 13.633 25.176 ;
     RECT  13.597 26.736 13.633 26.76 ;
     RECT  11.977 27.792 13.633 27.816 ;
     RECT  13.561 28.848 13.633 29.112 ;
     RECT  13.561 32.256 13.633 32.28 ;
     RECT  13.093 33.552 13.633 34.632 ;
     RECT  13.561 38.304 13.633 40.2 ;
     RECT  12.229 43.824 13.633 43.848 ;
     RECT  13.597 44.88 13.633 44.904 ;
     RECT  13.597 46.992 13.633 47.016 ;
     RECT  13.597 48.048 13.633 48.072 ;
     RECT  13.597 49.392 13.633 49.656 ;
     RECT  13.597 50.976 13.633 51 ;
     RECT  13.597 52.272 13.633 54.12 ;
     RECT  13.057 6.192 13.669 6.456 ;
     RECT  13.345 57.552 14.137 58.248 ;
     RECT  13.633 9.888 14.173 19.128 ;
     RECT  13.633 20.688 14.173 22.776 ;
     RECT  13.633 23.808 14.173 25.416 ;
     RECT  13.633 26.448 14.173 26.76 ;
     RECT  13.633 27.792 14.173 35.16 ;
     RECT  13.633 42 14.173 42.312 ;
     RECT  13.633 45.936 14.173 55.176 ;
     RECT  14.137 57.024 14.173 58.248 ;
     RECT  13.669 5.424 14.209 6.456 ;
     RECT  13.057 8.832 14.209 8.856 ;
     RECT  14.173 9.888 14.209 19.656 ;
     RECT  14.173 20.688 14.209 35.16 ;
     RECT  13.633 37.008 14.209 40.728 ;
     RECT  14.173 42 14.209 42.84 ;
     RECT  13.633 43.824 14.209 44.904 ;
     RECT  14.173 45.936 14.209 58.248 ;
     RECT  14.209 5.424 14.245 19.656 ;
     RECT  14.209 20.688 14.245 59.4 ;
     RECT  14.245 5.424 15.036 59.4 ;
    LAYER M5 ;
     RECT  0.192 1.285 0.216 1.381 ;
     RECT  0.096 1.381 0.216 1.427 ;
     RECT  2.4 2.137 2.52 2.151 ;
     RECT  5.1 2.137 5.22 2.151 ;
     RECT  7.8 2.137 7.92 2.151 ;
     RECT  10.5 2.137 10.62 2.151 ;
     RECT  7.8 2.151 8.112 5.653 ;
     RECT  2.4 2.151 2.712 6.229 ;
     RECT  3.936 5.461 3.96 6.229 ;
     RECT  7.392 5.653 8.112 6.277 ;
     RECT  7.056 6.277 8.112 6.709 ;
     RECT  10.5 2.151 10.812 6.805 ;
     RECT  2.4 6.229 3.96 7.141 ;
     RECT  5.1 2.151 5.412 7.141 ;
     RECT  7.056 6.709 8.904 7.235 ;
     RECT  2.4 7.141 5.412 7.907 ;
     RECT  3.936 7.907 5.412 9.011 ;
     RECT  4.896 9.011 5.412 9.299 ;
     RECT  7.8 7.235 8.904 9.397 ;
     RECT  7.248 9.397 8.904 10.019 ;
     RECT  5.1 9.299 5.412 10.357 ;
     RECT  7.248 10.019 8.328 10.837 ;
     RECT  6.816 10.837 8.328 11.123 ;
     RECT  4.992 10.357 5.412 11.699 ;
     RECT  6.816 11.123 8.232 12.517 ;
     RECT  10.32 6.805 10.812 12.755 ;
     RECT  6.624 12.517 8.232 13.093 ;
     RECT  6.624 13.093 8.856 13.715 ;
     RECT  2.4 7.907 2.712 14.101 ;
     RECT  7.8 13.715 8.856 14.339 ;
     RECT  5.1 11.699 5.412 14.389 ;
     RECT  4.944 14.389 5.412 15.637 ;
     RECT  6.624 13.715 6.648 15.829 ;
     RECT  7.8 14.339 8.232 15.829 ;
     RECT  2.4 14.101 3 16.019 ;
     RECT  10.368 12.755 10.812 17.891 ;
     RECT  6.624 15.829 8.232 18.467 ;
     RECT  4.176 15.637 5.412 18.707 ;
     RECT  4.944 18.707 5.412 18.805 ;
     RECT  4.944 18.805 6.312 18.851 ;
     RECT  7.392 18.467 8.232 18.851 ;
     RECT  3.936 18.997 3.96 19.285 ;
     RECT  3.888 19.285 3.96 20.341 ;
     RECT  5.1 18.851 6.312 20.341 ;
     RECT  7.8 18.851 8.232 20.485 ;
     RECT  3.888 20.341 6.312 20.725 ;
     RECT  3.888 20.725 6.696 21.061 ;
     RECT  7.8 20.485 8.664 21.061 ;
     RECT  10.5 17.891 10.812 21.493 ;
     RECT  3.888 21.061 8.664 21.683 ;
     RECT  6.672 21.683 8.664 22.883 ;
     RECT  3.888 21.683 5.688 24.131 ;
     RECT  2.4 16.019 2.712 25.045 ;
     RECT  3.888 24.131 5.412 25.045 ;
     RECT  6.672 22.883 8.112 25.045 ;
     RECT  9.888 21.493 10.812 25.573 ;
     RECT  2.4 25.045 5.412 25.715 ;
     RECT  6.48 25.045 8.112 25.715 ;
     RECT  9.84 25.573 10.812 26.053 ;
     RECT  9.168 26.053 10.812 26.675 ;
     RECT  6.672 25.715 8.112 26.773 ;
     RECT  9.168 26.675 9.192 26.773 ;
     RECT  6.672 26.773 9.192 27.203 ;
     RECT  4.944 25.715 5.412 27.349 ;
     RECT  6.672 27.203 8.856 27.349 ;
     RECT  2.4 25.715 3.912 27.637 ;
     RECT  10.5 26.675 10.812 27.733 ;
     RECT  4.944 27.349 8.856 27.971 ;
     RECT  6.864 27.971 8.856 28.547 ;
     RECT  4.944 27.971 5.736 29.027 ;
     RECT  6.864 28.547 8.808 29.123 ;
     RECT  4.944 29.027 5.412 29.171 ;
     RECT  10.224 27.733 10.812 29.699 ;
     RECT  0.096 1.427 0.12 30.229 ;
     RECT  0.096 30.229 0.264 30.275 ;
     RECT  0.24 30.275 0.264 30.419 ;
     RECT  6.864 29.123 8.112 30.709 ;
     RECT  6.864 30.709 8.52 30.851 ;
     RECT  4.992 29.171 5.412 30.899 ;
     RECT  5.1 30.899 5.412 31.573 ;
     RECT  2.4 27.637 3.96 31.955 ;
     RECT  10.272 29.699 10.812 31.955 ;
     RECT  5.1 31.573 5.688 32.821 ;
     RECT  10.5 31.955 10.812 32.917 ;
     RECT  7.104 30.851 8.52 33.013 ;
     RECT  6.864 33.013 8.856 34.069 ;
     RECT  4.992 32.821 5.688 34.835 ;
     RECT  6.816 34.069 8.856 35.173 ;
     RECT  2.4 31.955 3.912 35.269 ;
     RECT  2.4 35.269 3.96 36.805 ;
     RECT  5.1 34.835 5.412 36.805 ;
     RECT  6.72 35.173 8.856 36.997 ;
     RECT  10.32 32.917 10.812 39.301 ;
     RECT  2.4 36.805 5.412 41.075 ;
     RECT  6.624 36.997 8.856 41.075 ;
     RECT  7.632 41.075 8.856 41.699 ;
     RECT  2.4 41.075 3.96 41.747 ;
     RECT  6.624 41.075 6.648 42.037 ;
     RECT  7.632 41.699 8.112 42.037 ;
     RECT  2.4 41.747 3.432 43.379 ;
     RECT  4.992 41.075 5.412 43.571 ;
     RECT  6.624 42.037 8.112 44.869 ;
     RECT  6.624 44.869 8.856 45.155 ;
     RECT  5.1 43.571 5.412 45.541 ;
     RECT  7.392 45.155 8.856 45.683 ;
     RECT  3.936 44.965 3.96 46.069 ;
     RECT  4.992 45.541 5.412 46.069 ;
     RECT  10.272 39.301 10.812 46.643 ;
     RECT  3.936 46.069 5.412 46.787 ;
     RECT  7.632 45.683 8.856 46.787 ;
     RECT  7.632 46.787 8.112 47.221 ;
     RECT  4.416 46.787 5.412 47.651 ;
     RECT  7.248 47.221 8.112 47.891 ;
     RECT  4.992 47.651 5.412 48.373 ;
     RECT  7.584 47.891 8.112 48.949 ;
     RECT  7.392 48.949 8.112 48.997 ;
     RECT  4.992 48.373 5.64 49.477 ;
     RECT  2.4 43.379 2.712 50.101 ;
     RECT  7.392 48.997 8.904 50.437 ;
     RECT  10.368 46.643 10.812 50.531 ;
     RECT  4.992 49.477 5.688 50.579 ;
     RECT  2.4 50.101 3.432 50.629 ;
     RECT  5.1 50.579 5.688 50.771 ;
     RECT  7.2 50.437 8.904 50.771 ;
     RECT  2.4 50.629 3.96 51.347 ;
     RECT  3.888 51.347 3.912 51.923 ;
     RECT  5.1 50.771 5.412 52.405 ;
     RECT  7.2 50.771 8.112 52.499 ;
     RECT  10.5 50.531 10.812 52.741 ;
     RECT  5.1 52.405 5.688 53.557 ;
     RECT  7.296 52.499 8.112 53.603 ;
     RECT  3.936 53.269 3.96 53.893 ;
     RECT  5.1 53.557 5.88 54.563 ;
     RECT  3.888 53.893 3.96 54.755 ;
     RECT  7.8 53.603 8.112 55.141 ;
     RECT  6.816 55.141 8.112 55.237 ;
     RECT  3.936 54.755 3.96 55.331 ;
     RECT  10.368 52.741 10.812 55.331 ;
     RECT  5.1 54.563 5.412 55.765 ;
     RECT  6.816 55.237 8.232 55.907 ;
     RECT  7.8 55.907 8.232 57.635 ;
     RECT  4.896 55.765 5.412 59.315 ;
     RECT  2.4 51.347 2.712 62.649 ;
     RECT  5.1 59.315 5.412 62.649 ;
     RECT  7.8 57.635 8.112 62.649 ;
     RECT  10.5 55.331 10.812 62.649 ;
     RECT  2.4 62.649 2.52 62.663 ;
     RECT  5.1 62.649 5.22 62.663 ;
     RECT  7.8 62.649 7.92 62.663 ;
     RECT  10.5 62.649 10.62 62.663 ;
     RECT  2.712 5.461 3.936 6.229 ;
     RECT  3.96 5.461 5.1 7.141 ;
     RECT  8.904 6.805 10.32 10.019 ;
     RECT  2.712 7.907 3.936 9.011 ;
     RECT  4.992 9.299 5.1 10.357 ;
     RECT  5.412 10.837 6.816 12.517 ;
     RECT  5.412 12.517 6.624 18.467 ;
     RECT  10.32 12.755 10.368 13.093 ;
     RECT  8.856 13.093 10.368 14.339 ;
     RECT  6.648 13.715 7.8 15.829 ;
     RECT  3 15.637 4.176 16.019 ;
     RECT  2.712 16.019 4.176 18.707 ;
     RECT  5.412 18.467 7.392 18.805 ;
     RECT  2.712 18.707 4.944 18.851 ;
     RECT  6.312 18.805 7.392 18.851 ;
     RECT  2.712 18.851 5.1 18.997 ;
     RECT  6.312 18.851 7.8 20.725 ;
     RECT  2.712 18.997 3.936 19.285 ;
     RECT  3.96 18.997 5.1 20.341 ;
     RECT  2.712 19.285 3.888 25.045 ;
     RECT  6.696 20.725 7.8 21.061 ;
     RECT  8.664 21.493 9.888 22.883 ;
     RECT  5.688 21.683 6.672 24.131 ;
     RECT  5.412 24.131 6.672 25.045 ;
     RECT  5.412 25.045 6.48 25.715 ;
     RECT  3.912 25.715 4.944 27.637 ;
     RECT  5.412 25.715 6.672 27.349 ;
     RECT  8.112 26.053 9.168 26.773 ;
     RECT  9.192 26.675 10.5 27.203 ;
     RECT  8.856 27.203 10.5 27.733 ;
     RECT  3.96 27.637 4.944 29.171 ;
     RECT  8.856 27.733 10.224 28.547 ;
     RECT  5.736 27.971 6.864 29.027 ;
     RECT  8.808 28.547 10.224 29.123 ;
     RECT  5.412 29.027 6.864 30.851 ;
     RECT  3.96 29.171 4.992 30.899 ;
     RECT  5.412 30.851 7.104 31.573 ;
     RECT  3.96 30.899 5.1 31.955 ;
     RECT  5.688 31.573 7.104 33.013 ;
     RECT  3.912 31.955 5.1 32.821 ;
     RECT  10.272 31.955 10.5 32.917 ;
     RECT  3.912 32.821 4.992 34.835 ;
     RECT  10.272 32.917 10.32 33.013 ;
     RECT  5.688 33.013 6.864 34.069 ;
     RECT  8.856 33.013 10.32 39.301 ;
     RECT  5.688 34.069 6.816 34.835 ;
     RECT  3.912 34.835 5.1 35.269 ;
     RECT  5.412 34.835 6.816 35.173 ;
     RECT  5.412 35.173 6.72 36.997 ;
     RECT  3.96 35.269 5.1 36.805 ;
     RECT  5.412 36.997 6.624 45.155 ;
     RECT  8.856 39.301 10.272 41.699 ;
     RECT  3.96 41.075 4.992 41.747 ;
     RECT  6.648 41.075 7.632 42.037 ;
     RECT  4.992 43.571 5.1 44.965 ;
     RECT  8.856 44.869 10.272 46.643 ;
     RECT  2.712 44.965 3.936 46.787 ;
     RECT  3.96 44.965 5.1 45.541 ;
     RECT  3.96 45.541 4.992 46.069 ;
     RECT  8.856 46.643 10.368 46.787 ;
     RECT  7.392 47.891 7.584 48.949 ;
     RECT  8.904 48.997 10.368 50.531 ;
     RECT  5.688 50.437 7.2 50.771 ;
     RECT  4.992 50.579 5.1 50.629 ;
     RECT  3.96 50.629 5.1 51.347 ;
     RECT  2.712 51.347 3.888 51.923 ;
     RECT  3.912 51.347 5.1 51.923 ;
     RECT  2.712 51.923 5.1 53.269 ;
     RECT  5.688 52.405 7.2 52.499 ;
     RECT  5.688 52.499 7.296 53.557 ;
     RECT  2.712 53.269 3.936 53.893 ;
     RECT  3.96 53.269 5.1 55.331 ;
     RECT  5.88 53.557 7.296 53.603 ;
     RECT  2.712 53.893 3.888 54.755 ;
     RECT  5.412 54.563 5.88 55.141 ;
     RECT  2.712 54.755 3.936 55.331 ;
     RECT  5.412 55.141 6.816 55.907 ;
     RECT  4.896 55.331 5.1 55.765 ;
  END
END qwen_tx_rnen_r0
END LIBRARY
